VERSION 5.8 ;
BUSBITCHARS "[]" ;
DIVIDERCHAR "/" ;
UNITS
    DATABASE MICRONS 1000 ;
END UNITS

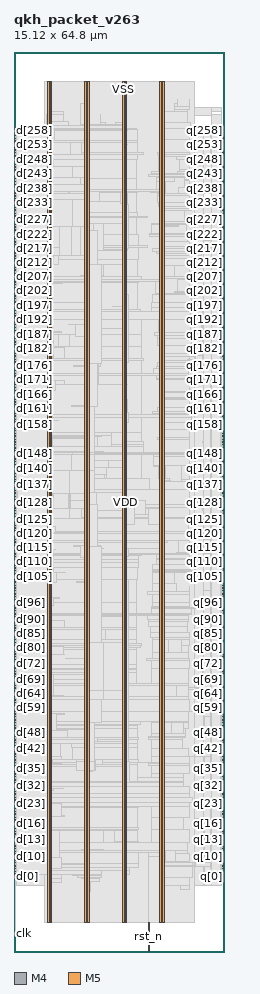
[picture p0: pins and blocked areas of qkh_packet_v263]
MACRO qkh_packet_v263
  FOREIGN qkh_packet_v263 0 0 ;
  CLASS BLOCK ;
  SIZE 15.12 BY 64.8 ;
  PIN clk
    DIRECTION INPUT ;
    USE SIGNAL ;
    PORT
      LAYER M4 ;
        RECT  0.054 1.296 0.138 1.32 ;
    END
    PORT
      LAYER M4 ;
        RECT  0.108 1.296 0.227 1.416 ;
    END
  END clk
  PIN d[0]
    DIRECTION INPUT ;
    USE SIGNAL ;
    PORT
      LAYER M4 ;
        RECT  0.054 5.424 0.138 5.448 ;
    END
  END d[0]
  PIN d[100]
    DIRECTION INPUT ;
    USE SIGNAL ;
    PORT
      LAYER M4 ;
        RECT  0.054 26.016 0.138 26.04 ;
    END
  END d[100]
  PIN d[101]
    DIRECTION INPUT ;
    USE SIGNAL ;
    PORT
      LAYER M4 ;
        RECT  0.054 26.208 0.138 26.232 ;
    END
  END d[101]
  PIN d[102]
    DIRECTION INPUT ;
    USE SIGNAL ;
    PORT
      LAYER M4 ;
        RECT  0.054 26.4 0.138 26.424 ;
    END
  END d[102]
  PIN d[103]
    DIRECTION INPUT ;
    USE SIGNAL ;
    PORT
      LAYER M4 ;
        RECT  0.054 26.64 0.138 26.664 ;
    END
  END d[103]
  PIN d[104]
    DIRECTION INPUT ;
    USE SIGNAL ;
    PORT
      LAYER M4 ;
        RECT  0.054 26.832 0.138 26.856 ;
    END
  END d[104]
  PIN d[105]
    DIRECTION INPUT ;
    USE SIGNAL ;
    PORT
      LAYER M4 ;
        RECT  0.054 27.024 0.138 27.048 ;
    END
  END d[105]
  PIN d[106]
    DIRECTION INPUT ;
    USE SIGNAL ;
    PORT
      LAYER M4 ;
        RECT  0.054 27.216 0.138 27.24 ;
    END
  END d[106]
  PIN d[107]
    DIRECTION INPUT ;
    USE SIGNAL ;
    PORT
      LAYER M4 ;
        RECT  0.054 27.456 0.138 27.48 ;
    END
  END d[107]
  PIN d[108]
    DIRECTION INPUT ;
    USE SIGNAL ;
    PORT
      LAYER M4 ;
        RECT  0.054 27.648 0.138 27.672 ;
    END
  END d[108]
  PIN d[109]
    DIRECTION INPUT ;
    USE SIGNAL ;
    PORT
      LAYER M4 ;
        RECT  0.054 27.84 0.138 27.864 ;
    END
  END d[109]
  PIN d[10]
    DIRECTION INPUT ;
    USE SIGNAL ;
    PORT
      LAYER M4 ;
        RECT  0.054 7.44 0.138 7.464 ;
    END
  END d[10]
  PIN d[110]
    DIRECTION INPUT ;
    USE SIGNAL ;
    PORT
      LAYER M4 ;
        RECT  0.054 28.08 0.138 28.104 ;
    END
  END d[110]
  PIN d[111]
    DIRECTION INPUT ;
    USE SIGNAL ;
    PORT
      LAYER M4 ;
        RECT  0.054 28.272 0.138 28.296 ;
    END
  END d[111]
  PIN d[112]
    DIRECTION INPUT ;
    USE SIGNAL ;
    PORT
      LAYER M4 ;
        RECT  0.054 28.464 0.138 28.488 ;
    END
  END d[112]
  PIN d[113]
    DIRECTION INPUT ;
    USE SIGNAL ;
    PORT
      LAYER M4 ;
        RECT  0.054 28.656 0.138 28.68 ;
    END
  END d[113]
  PIN d[114]
    DIRECTION INPUT ;
    USE SIGNAL ;
    PORT
      LAYER M4 ;
        RECT  0.054 28.896 0.138 28.92 ;
    END
  END d[114]
  PIN d[115]
    DIRECTION INPUT ;
    USE SIGNAL ;
    PORT
      LAYER M4 ;
        RECT  0.054 29.088 0.138 29.112 ;
    END
  END d[115]
  PIN d[116]
    DIRECTION INPUT ;
    USE SIGNAL ;
    PORT
      LAYER M4 ;
        RECT  0.054 29.28 0.138 29.304 ;
    END
  END d[116]
  PIN d[117]
    DIRECTION INPUT ;
    USE SIGNAL ;
    PORT
      LAYER M4 ;
        RECT  0.054 29.52 0.138 29.544 ;
    END
  END d[117]
  PIN d[118]
    DIRECTION INPUT ;
    USE SIGNAL ;
    PORT
      LAYER M4 ;
        RECT  0.054 29.712 0.138 29.736 ;
    END
  END d[118]
  PIN d[119]
    DIRECTION INPUT ;
    USE SIGNAL ;
    PORT
      LAYER M4 ;
        RECT  0.054 29.904 0.138 29.928 ;
    END
  END d[119]
  PIN d[11]
    DIRECTION INPUT ;
    USE SIGNAL ;
    PORT
      LAYER M4 ;
        RECT  0.054 7.632 0.138 7.656 ;
    END
  END d[11]
  PIN d[120]
    DIRECTION INPUT ;
    USE SIGNAL ;
    PORT
      LAYER M4 ;
        RECT  0.054 30.144 0.138 30.168 ;
    END
  END d[120]
  PIN d[121]
    DIRECTION INPUT ;
    USE SIGNAL ;
    PORT
      LAYER M4 ;
        RECT  0.054 30.336 0.138 30.36 ;
    END
  END d[121]
  PIN d[122]
    DIRECTION INPUT ;
    USE SIGNAL ;
    PORT
      LAYER M4 ;
        RECT  0.054 30.528 0.138 30.552 ;
    END
  END d[122]
  PIN d[123]
    DIRECTION INPUT ;
    USE SIGNAL ;
    PORT
      LAYER M4 ;
        RECT  0.054 30.72 0.138 30.744 ;
    END
  END d[123]
  PIN d[124]
    DIRECTION INPUT ;
    USE SIGNAL ;
    PORT
      LAYER M4 ;
        RECT  0.054 30.96 0.138 30.984 ;
    END
  END d[124]
  PIN d[125]
    DIRECTION INPUT ;
    USE SIGNAL ;
    PORT
      LAYER M4 ;
        RECT  0.054 31.152 0.138 31.176 ;
    END
  END d[125]
  PIN d[126]
    DIRECTION INPUT ;
    USE SIGNAL ;
    PORT
      LAYER M4 ;
        RECT  0.054 31.344 0.138 31.368 ;
    END
  END d[126]
  PIN d[127]
    DIRECTION INPUT ;
    USE SIGNAL ;
    PORT
      LAYER M4 ;
        RECT  0.054 31.584 0.138 31.608 ;
    END
  END d[127]
  PIN d[128]
    DIRECTION INPUT ;
    USE SIGNAL ;
    PORT
      LAYER M4 ;
        RECT  0.054 31.776 0.138 31.8 ;
    END
  END d[128]
  PIN d[129]
    DIRECTION INPUT ;
    USE SIGNAL ;
    PORT
      LAYER M4 ;
        RECT  0.054 31.968 0.138 31.992 ;
    END
  END d[129]
  PIN d[12]
    DIRECTION INPUT ;
    USE SIGNAL ;
    PORT
      LAYER M4 ;
        RECT  0.054 7.872 0.138 7.896 ;
    END
  END d[12]
  PIN d[130]
    DIRECTION INPUT ;
    USE SIGNAL ;
    PORT
      LAYER M4 ;
        RECT  0.054 32.16 0.138 32.184 ;
    END
  END d[130]
  PIN d[131]
    DIRECTION INPUT ;
    USE SIGNAL ;
    PORT
      LAYER M4 ;
        RECT  0.054 32.4 0.138 32.424 ;
    END
  END d[131]
  PIN d[132]
    DIRECTION INPUT ;
    USE SIGNAL ;
    PORT
      LAYER M4 ;
        RECT  0.054 32.592 0.138 32.616 ;
    END
  END d[132]
  PIN d[133]
    DIRECTION INPUT ;
    USE SIGNAL ;
    PORT
      LAYER M4 ;
        RECT  0.054 32.784 0.138 32.808 ;
    END
  END d[133]
  PIN d[134]
    DIRECTION INPUT ;
    USE SIGNAL ;
    PORT
      LAYER M4 ;
        RECT  0.054 33.024 0.138 33.048 ;
    END
  END d[134]
  PIN d[135]
    DIRECTION INPUT ;
    USE SIGNAL ;
    PORT
      LAYER M4 ;
        RECT  0.054 33.216 0.138 33.24 ;
    END
  END d[135]
  PIN d[136]
    DIRECTION INPUT ;
    USE SIGNAL ;
    PORT
      LAYER M4 ;
        RECT  0.054 33.408 0.138 33.432 ;
    END
  END d[136]
  PIN d[137]
    DIRECTION INPUT ;
    USE SIGNAL ;
    PORT
      LAYER M4 ;
        RECT  0.054 33.648 0.138 33.672 ;
    END
  END d[137]
  PIN d[138]
    DIRECTION INPUT ;
    USE SIGNAL ;
    PORT
      LAYER M4 ;
        RECT  0.054 33.84 0.138 33.864 ;
    END
  END d[138]
  PIN d[139]
    DIRECTION INPUT ;
    USE SIGNAL ;
    PORT
      LAYER M4 ;
        RECT  0.054 34.032 0.138 34.056 ;
    END
  END d[139]
  PIN d[13]
    DIRECTION INPUT ;
    USE SIGNAL ;
    PORT
      LAYER M4 ;
        RECT  0.054 8.064 0.138 8.088 ;
    END
  END d[13]
  PIN d[140]
    DIRECTION INPUT ;
    USE SIGNAL ;
    PORT
      LAYER M4 ;
        RECT  0.054 34.224 0.138 34.248 ;
    END
  END d[140]
  PIN d[141]
    DIRECTION INPUT ;
    USE SIGNAL ;
    PORT
      LAYER M4 ;
        RECT  0.054 34.464 0.138 34.488 ;
    END
  END d[141]
  PIN d[142]
    DIRECTION INPUT ;
    USE SIGNAL ;
    PORT
      LAYER M4 ;
        RECT  0.054 34.656 0.138 34.68 ;
    END
  END d[142]
  PIN d[143]
    DIRECTION INPUT ;
    USE SIGNAL ;
    PORT
      LAYER M4 ;
        RECT  0.054 34.848 0.138 34.872 ;
    END
  END d[143]
  PIN d[144]
    DIRECTION INPUT ;
    USE SIGNAL ;
    PORT
      LAYER M4 ;
        RECT  0.054 35.088 0.138 35.112 ;
    END
  END d[144]
  PIN d[145]
    DIRECTION INPUT ;
    USE SIGNAL ;
    PORT
      LAYER M4 ;
        RECT  0.054 35.28 0.138 35.304 ;
    END
  END d[145]
  PIN d[146]
    DIRECTION INPUT ;
    USE SIGNAL ;
    PORT
      LAYER M4 ;
        RECT  0.054 35.472 0.138 35.496 ;
    END
  END d[146]
  PIN d[147]
    DIRECTION INPUT ;
    USE SIGNAL ;
    PORT
      LAYER M4 ;
        RECT  0.054 35.664 0.138 35.688 ;
    END
  END d[147]
  PIN d[148]
    DIRECTION INPUT ;
    USE SIGNAL ;
    PORT
      LAYER M4 ;
        RECT  0.054 35.904 0.138 35.928 ;
    END
  END d[148]
  PIN d[149]
    DIRECTION INPUT ;
    USE SIGNAL ;
    PORT
      LAYER M4 ;
        RECT  0.054 36.096 0.138 36.12 ;
    END
  END d[149]
  PIN d[14]
    DIRECTION INPUT ;
    USE SIGNAL ;
    PORT
      LAYER M4 ;
        RECT  0.054 8.256 0.138 8.28 ;
    END
  END d[14]
  PIN d[150]
    DIRECTION INPUT ;
    USE SIGNAL ;
    PORT
      LAYER M4 ;
        RECT  0.054 36.288 0.138 36.312 ;
    END
  END d[150]
  PIN d[151]
    DIRECTION INPUT ;
    USE SIGNAL ;
    PORT
      LAYER M4 ;
        RECT  0.054 36.528 0.138 36.552 ;
    END
  END d[151]
  PIN d[152]
    DIRECTION INPUT ;
    USE SIGNAL ;
    PORT
      LAYER M4 ;
        RECT  0.054 36.72 0.138 36.744 ;
    END
  END d[152]
  PIN d[153]
    DIRECTION INPUT ;
    USE SIGNAL ;
    PORT
      LAYER M4 ;
        RECT  0.054 36.912 0.138 36.936 ;
    END
  END d[153]
  PIN d[154]
    DIRECTION INPUT ;
    USE SIGNAL ;
    PORT
      LAYER M4 ;
        RECT  0.054 37.152 0.138 37.176 ;
    END
  END d[154]
  PIN d[155]
    DIRECTION INPUT ;
    USE SIGNAL ;
    PORT
      LAYER M4 ;
        RECT  0.054 37.344 0.138 37.368 ;
    END
  END d[155]
  PIN d[156]
    DIRECTION INPUT ;
    USE SIGNAL ;
    PORT
      LAYER M4 ;
        RECT  0.054 37.536 0.138 37.56 ;
    END
  END d[156]
  PIN d[157]
    DIRECTION INPUT ;
    USE SIGNAL ;
    PORT
      LAYER M4 ;
        RECT  0.054 37.728 0.138 37.752 ;
    END
  END d[157]
  PIN d[158]
    DIRECTION INPUT ;
    USE SIGNAL ;
    PORT
      LAYER M4 ;
        RECT  0.054 37.968 0.138 37.992 ;
    END
  END d[158]
  PIN d[159]
    DIRECTION INPUT ;
    USE SIGNAL ;
    PORT
      LAYER M4 ;
        RECT  0.054 38.16 0.138 38.184 ;
    END
  END d[159]
  PIN d[15]
    DIRECTION INPUT ;
    USE SIGNAL ;
    PORT
      LAYER M4 ;
        RECT  0.054 8.496 0.138 8.52 ;
    END
  END d[15]
  PIN d[160]
    DIRECTION INPUT ;
    USE SIGNAL ;
    PORT
      LAYER M4 ;
        RECT  0.054 38.352 0.138 38.376 ;
    END
  END d[160]
  PIN d[161]
    DIRECTION INPUT ;
    USE SIGNAL ;
    PORT
      LAYER M4 ;
        RECT  0.054 38.592 0.138 38.616 ;
    END
  END d[161]
  PIN d[162]
    DIRECTION INPUT ;
    USE SIGNAL ;
    PORT
      LAYER M4 ;
        RECT  0.054 38.784 0.138 38.808 ;
    END
  END d[162]
  PIN d[163]
    DIRECTION INPUT ;
    USE SIGNAL ;
    PORT
      LAYER M4 ;
        RECT  0.054 38.976 0.138 39 ;
    END
  END d[163]
  PIN d[164]
    DIRECTION INPUT ;
    USE SIGNAL ;
    PORT
      LAYER M4 ;
        RECT  0.054 39.168 0.138 39.192 ;
    END
  END d[164]
  PIN d[165]
    DIRECTION INPUT ;
    USE SIGNAL ;
    PORT
      LAYER M4 ;
        RECT  0.054 39.408 0.138 39.432 ;
    END
  END d[165]
  PIN d[166]
    DIRECTION INPUT ;
    USE SIGNAL ;
    PORT
      LAYER M4 ;
        RECT  0.054 39.6 0.138 39.624 ;
    END
  END d[166]
  PIN d[167]
    DIRECTION INPUT ;
    USE SIGNAL ;
    PORT
      LAYER M4 ;
        RECT  0.054 39.792 0.138 39.816 ;
    END
  END d[167]
  PIN d[168]
    DIRECTION INPUT ;
    USE SIGNAL ;
    PORT
      LAYER M4 ;
        RECT  0.054 40.032 0.138 40.056 ;
    END
  END d[168]
  PIN d[169]
    DIRECTION INPUT ;
    USE SIGNAL ;
    PORT
      LAYER M4 ;
        RECT  0.054 40.224 0.138 40.248 ;
    END
  END d[169]
  PIN d[16]
    DIRECTION INPUT ;
    USE SIGNAL ;
    PORT
      LAYER M4 ;
        RECT  0.054 8.688 0.138 8.712 ;
    END
  END d[16]
  PIN d[170]
    DIRECTION INPUT ;
    USE SIGNAL ;
    PORT
      LAYER M4 ;
        RECT  0.054 40.416 0.138 40.44 ;
    END
  END d[170]
  PIN d[171]
    DIRECTION INPUT ;
    USE SIGNAL ;
    PORT
      LAYER M4 ;
        RECT  0.054 40.656 0.138 40.68 ;
    END
  END d[171]
  PIN d[172]
    DIRECTION INPUT ;
    USE SIGNAL ;
    PORT
      LAYER M4 ;
        RECT  0.054 40.848 0.138 40.872 ;
    END
  END d[172]
  PIN d[173]
    DIRECTION INPUT ;
    USE SIGNAL ;
    PORT
      LAYER M4 ;
        RECT  0.054 41.04 0.138 41.064 ;
    END
  END d[173]
  PIN d[174]
    DIRECTION INPUT ;
    USE SIGNAL ;
    PORT
      LAYER M4 ;
        RECT  0.054 41.232 0.138 41.256 ;
    END
  END d[174]
  PIN d[175]
    DIRECTION INPUT ;
    USE SIGNAL ;
    PORT
      LAYER M4 ;
        RECT  0.054 41.472 0.138 41.496 ;
    END
  END d[175]
  PIN d[176]
    DIRECTION INPUT ;
    USE SIGNAL ;
    PORT
      LAYER M4 ;
        RECT  0.054 41.664 0.138 41.688 ;
    END
  END d[176]
  PIN d[177]
    DIRECTION INPUT ;
    USE SIGNAL ;
    PORT
      LAYER M4 ;
        RECT  0.054 41.856 0.138 41.88 ;
    END
  END d[177]
  PIN d[178]
    DIRECTION INPUT ;
    USE SIGNAL ;
    PORT
      LAYER M4 ;
        RECT  0.054 42.096 0.138 42.12 ;
    END
  END d[178]
  PIN d[179]
    DIRECTION INPUT ;
    USE SIGNAL ;
    PORT
      LAYER M4 ;
        RECT  0.054 42.288 0.138 42.312 ;
    END
  END d[179]
  PIN d[17]
    DIRECTION INPUT ;
    USE SIGNAL ;
    PORT
      LAYER M4 ;
        RECT  0.054 8.88 0.138 8.904 ;
    END
  END d[17]
  PIN d[180]
    DIRECTION INPUT ;
    USE SIGNAL ;
    PORT
      LAYER M4 ;
        RECT  0.054 42.48 0.138 42.504 ;
    END
  END d[180]
  PIN d[181]
    DIRECTION INPUT ;
    USE SIGNAL ;
    PORT
      LAYER M4 ;
        RECT  0.054 42.672 0.138 42.696 ;
    END
  END d[181]
  PIN d[182]
    DIRECTION INPUT ;
    USE SIGNAL ;
    PORT
      LAYER M4 ;
        RECT  0.054 42.912 0.138 42.936 ;
    END
  END d[182]
  PIN d[183]
    DIRECTION INPUT ;
    USE SIGNAL ;
    PORT
      LAYER M4 ;
        RECT  0.054 43.104 0.138 43.128 ;
    END
  END d[183]
  PIN d[184]
    DIRECTION INPUT ;
    USE SIGNAL ;
    PORT
      LAYER M4 ;
        RECT  0.054 43.296 0.138 43.32 ;
    END
  END d[184]
  PIN d[185]
    DIRECTION INPUT ;
    USE SIGNAL ;
    PORT
      LAYER M4 ;
        RECT  0.054 43.536 0.138 43.56 ;
    END
  END d[185]
  PIN d[186]
    DIRECTION INPUT ;
    USE SIGNAL ;
    PORT
      LAYER M4 ;
        RECT  0.054 43.728 0.138 43.752 ;
    END
  END d[186]
  PIN d[187]
    DIRECTION INPUT ;
    USE SIGNAL ;
    PORT
      LAYER M4 ;
        RECT  0.054 43.92 0.138 43.944 ;
    END
  END d[187]
  PIN d[188]
    DIRECTION INPUT ;
    USE SIGNAL ;
    PORT
      LAYER M4 ;
        RECT  0.054 44.16 0.138 44.184 ;
    END
  END d[188]
  PIN d[189]
    DIRECTION INPUT ;
    USE SIGNAL ;
    PORT
      LAYER M4 ;
        RECT  0.054 44.352 0.138 44.376 ;
    END
  END d[189]
  PIN d[18]
    DIRECTION INPUT ;
    USE SIGNAL ;
    PORT
      LAYER M4 ;
        RECT  0.054 9.12 0.138 9.144 ;
    END
  END d[18]
  PIN d[190]
    DIRECTION INPUT ;
    USE SIGNAL ;
    PORT
      LAYER M4 ;
        RECT  0.054 44.544 0.138 44.568 ;
    END
  END d[190]
  PIN d[191]
    DIRECTION INPUT ;
    USE SIGNAL ;
    PORT
      LAYER M4 ;
        RECT  0.054 44.736 0.138 44.76 ;
    END
  END d[191]
  PIN d[192]
    DIRECTION INPUT ;
    USE SIGNAL ;
    PORT
      LAYER M4 ;
        RECT  0.054 44.976 0.138 45 ;
    END
  END d[192]
  PIN d[193]
    DIRECTION INPUT ;
    USE SIGNAL ;
    PORT
      LAYER M4 ;
        RECT  0.054 45.168 0.138 45.192 ;
    END
  END d[193]
  PIN d[194]
    DIRECTION INPUT ;
    USE SIGNAL ;
    PORT
      LAYER M4 ;
        RECT  0.054 45.36 0.138 45.384 ;
    END
  END d[194]
  PIN d[195]
    DIRECTION INPUT ;
    USE SIGNAL ;
    PORT
      LAYER M4 ;
        RECT  0.054 45.6 0.138 45.624 ;
    END
  END d[195]
  PIN d[196]
    DIRECTION INPUT ;
    USE SIGNAL ;
    PORT
      LAYER M4 ;
        RECT  0.054 45.792 0.138 45.816 ;
    END
  END d[196]
  PIN d[197]
    DIRECTION INPUT ;
    USE SIGNAL ;
    PORT
      LAYER M4 ;
        RECT  0.054 45.984 0.138 46.008 ;
    END
  END d[197]
  PIN d[198]
    DIRECTION INPUT ;
    USE SIGNAL ;
    PORT
      LAYER M4 ;
        RECT  0.054 46.176 0.138 46.2 ;
    END
  END d[198]
  PIN d[199]
    DIRECTION INPUT ;
    USE SIGNAL ;
    PORT
      LAYER M4 ;
        RECT  0.054 46.416 0.138 46.44 ;
    END
  END d[199]
  PIN d[19]
    DIRECTION INPUT ;
    USE SIGNAL ;
    PORT
      LAYER M4 ;
        RECT  0.054 9.312 0.138 9.336 ;
    END
  END d[19]
  PIN d[1]
    DIRECTION INPUT ;
    USE SIGNAL ;
    PORT
      LAYER M4 ;
        RECT  0.054 5.616 0.138 5.64 ;
    END
  END d[1]
  PIN d[200]
    DIRECTION INPUT ;
    USE SIGNAL ;
    PORT
      LAYER M4 ;
        RECT  0.054 46.608 0.138 46.632 ;
    END
  END d[200]
  PIN d[201]
    DIRECTION INPUT ;
    USE SIGNAL ;
    PORT
      LAYER M4 ;
        RECT  0.054 46.8 0.138 46.824 ;
    END
  END d[201]
  PIN d[202]
    DIRECTION INPUT ;
    USE SIGNAL ;
    PORT
      LAYER M4 ;
        RECT  0.054 47.04 0.138 47.064 ;
    END
  END d[202]
  PIN d[203]
    DIRECTION INPUT ;
    USE SIGNAL ;
    PORT
      LAYER M4 ;
        RECT  0.054 47.232 0.138 47.256 ;
    END
  END d[203]
  PIN d[204]
    DIRECTION INPUT ;
    USE SIGNAL ;
    PORT
      LAYER M4 ;
        RECT  0.054 47.424 0.138 47.448 ;
    END
  END d[204]
  PIN d[205]
    DIRECTION INPUT ;
    USE SIGNAL ;
    PORT
      LAYER M4 ;
        RECT  0.054 47.616 0.138 47.64 ;
    END
  END d[205]
  PIN d[206]
    DIRECTION INPUT ;
    USE SIGNAL ;
    PORT
      LAYER M4 ;
        RECT  0.054 47.856 0.138 47.88 ;
    END
  END d[206]
  PIN d[207]
    DIRECTION INPUT ;
    USE SIGNAL ;
    PORT
      LAYER M4 ;
        RECT  0.054 48.048 0.138 48.072 ;
    END
  END d[207]
  PIN d[208]
    DIRECTION INPUT ;
    USE SIGNAL ;
    PORT
      LAYER M4 ;
        RECT  0.054 48.24 0.138 48.264 ;
    END
  END d[208]
  PIN d[209]
    DIRECTION INPUT ;
    USE SIGNAL ;
    PORT
      LAYER M4 ;
        RECT  0.054 48.48 0.138 48.504 ;
    END
  END d[209]
  PIN d[20]
    DIRECTION INPUT ;
    USE SIGNAL ;
    PORT
      LAYER M4 ;
        RECT  0.054 9.504 0.138 9.528 ;
    END
  END d[20]
  PIN d[210]
    DIRECTION INPUT ;
    USE SIGNAL ;
    PORT
      LAYER M4 ;
        RECT  0.054 48.672 0.138 48.696 ;
    END
  END d[210]
  PIN d[211]
    DIRECTION INPUT ;
    USE SIGNAL ;
    PORT
      LAYER M4 ;
        RECT  0.054 48.864 0.138 48.888 ;
    END
  END d[211]
  PIN d[212]
    DIRECTION INPUT ;
    USE SIGNAL ;
    PORT
      LAYER M4 ;
        RECT  0.054 49.104 0.138 49.128 ;
    END
  END d[212]
  PIN d[213]
    DIRECTION INPUT ;
    USE SIGNAL ;
    PORT
      LAYER M4 ;
        RECT  0.054 49.296 0.138 49.32 ;
    END
  END d[213]
  PIN d[214]
    DIRECTION INPUT ;
    USE SIGNAL ;
    PORT
      LAYER M4 ;
        RECT  0.054 49.488 0.138 49.512 ;
    END
  END d[214]
  PIN d[215]
    DIRECTION INPUT ;
    USE SIGNAL ;
    PORT
      LAYER M4 ;
        RECT  0.054 49.68 0.138 49.704 ;
    END
  END d[215]
  PIN d[216]
    DIRECTION INPUT ;
    USE SIGNAL ;
    PORT
      LAYER M4 ;
        RECT  0.054 49.92 0.138 49.944 ;
    END
  END d[216]
  PIN d[217]
    DIRECTION INPUT ;
    USE SIGNAL ;
    PORT
      LAYER M4 ;
        RECT  0.054 50.112 0.138 50.136 ;
    END
  END d[217]
  PIN d[218]
    DIRECTION INPUT ;
    USE SIGNAL ;
    PORT
      LAYER M4 ;
        RECT  0.054 50.304 0.138 50.328 ;
    END
  END d[218]
  PIN d[219]
    DIRECTION INPUT ;
    USE SIGNAL ;
    PORT
      LAYER M4 ;
        RECT  0.054 50.544 0.138 50.568 ;
    END
  END d[219]
  PIN d[21]
    DIRECTION INPUT ;
    USE SIGNAL ;
    PORT
      LAYER M4 ;
        RECT  0.054 9.696 0.138 9.72 ;
    END
  END d[21]
  PIN d[220]
    DIRECTION INPUT ;
    USE SIGNAL ;
    PORT
      LAYER M4 ;
        RECT  0.054 50.736 0.138 50.76 ;
    END
  END d[220]
  PIN d[221]
    DIRECTION INPUT ;
    USE SIGNAL ;
    PORT
      LAYER M4 ;
        RECT  0.054 50.928 0.138 50.952 ;
    END
  END d[221]
  PIN d[222]
    DIRECTION INPUT ;
    USE SIGNAL ;
    PORT
      LAYER M4 ;
        RECT  0.054 51.12 0.138 51.144 ;
    END
  END d[222]
  PIN d[223]
    DIRECTION INPUT ;
    USE SIGNAL ;
    PORT
      LAYER M4 ;
        RECT  0.054 51.36 0.138 51.384 ;
    END
  END d[223]
  PIN d[224]
    DIRECTION INPUT ;
    USE SIGNAL ;
    PORT
      LAYER M4 ;
        RECT  0.054 51.552 0.138 51.576 ;
    END
  END d[224]
  PIN d[225]
    DIRECTION INPUT ;
    USE SIGNAL ;
    PORT
      LAYER M4 ;
        RECT  0.054 51.744 0.138 51.768 ;
    END
  END d[225]
  PIN d[226]
    DIRECTION INPUT ;
    USE SIGNAL ;
    PORT
      LAYER M4 ;
        RECT  0.054 51.984 0.138 52.008 ;
    END
  END d[226]
  PIN d[227]
    DIRECTION INPUT ;
    USE SIGNAL ;
    PORT
      LAYER M4 ;
        RECT  0.054 52.176 0.138 52.2 ;
    END
  END d[227]
  PIN d[228]
    DIRECTION INPUT ;
    USE SIGNAL ;
    PORT
      LAYER M4 ;
        RECT  0.054 52.368 0.138 52.392 ;
    END
  END d[228]
  PIN d[229]
    DIRECTION INPUT ;
    USE SIGNAL ;
    PORT
      LAYER M4 ;
        RECT  0.054 52.608 0.138 52.632 ;
    END
  END d[229]
  PIN d[22]
    DIRECTION INPUT ;
    USE SIGNAL ;
    PORT
      LAYER M4 ;
        RECT  0.054 9.936 0.138 9.96 ;
    END
  END d[22]
  PIN d[230]
    DIRECTION INPUT ;
    USE SIGNAL ;
    PORT
      LAYER M4 ;
        RECT  0.054 52.8 0.138 52.824 ;
    END
  END d[230]
  PIN d[231]
    DIRECTION INPUT ;
    USE SIGNAL ;
    PORT
      LAYER M4 ;
        RECT  0.054 52.992 0.138 53.016 ;
    END
  END d[231]
  PIN d[232]
    DIRECTION INPUT ;
    USE SIGNAL ;
    PORT
      LAYER M4 ;
        RECT  0.054 53.184 0.138 53.208 ;
    END
  END d[232]
  PIN d[233]
    DIRECTION INPUT ;
    USE SIGNAL ;
    PORT
      LAYER M4 ;
        RECT  0.054 53.424 0.138 53.448 ;
    END
  END d[233]
  PIN d[234]
    DIRECTION INPUT ;
    USE SIGNAL ;
    PORT
      LAYER M4 ;
        RECT  0.054 53.616 0.138 53.64 ;
    END
  END d[234]
  PIN d[235]
    DIRECTION INPUT ;
    USE SIGNAL ;
    PORT
      LAYER M4 ;
        RECT  0.054 53.808 0.138 53.832 ;
    END
  END d[235]
  PIN d[236]
    DIRECTION INPUT ;
    USE SIGNAL ;
    PORT
      LAYER M4 ;
        RECT  0.054 54.048 0.138 54.072 ;
    END
  END d[236]
  PIN d[237]
    DIRECTION INPUT ;
    USE SIGNAL ;
    PORT
      LAYER M4 ;
        RECT  0.054 54.24 0.138 54.264 ;
    END
  END d[237]
  PIN d[238]
    DIRECTION INPUT ;
    USE SIGNAL ;
    PORT
      LAYER M4 ;
        RECT  0.054 54.432 0.138 54.456 ;
    END
  END d[238]
  PIN d[239]
    DIRECTION INPUT ;
    USE SIGNAL ;
    PORT
      LAYER M4 ;
        RECT  0.054 54.624 0.138 54.648 ;
    END
  END d[239]
  PIN d[23]
    DIRECTION INPUT ;
    USE SIGNAL ;
    PORT
      LAYER M4 ;
        RECT  0.054 10.128 0.138 10.152 ;
    END
  END d[23]
  PIN d[240]
    DIRECTION INPUT ;
    USE SIGNAL ;
    PORT
      LAYER M4 ;
        RECT  0.054 54.864 0.138 54.888 ;
    END
  END d[240]
  PIN d[241]
    DIRECTION INPUT ;
    USE SIGNAL ;
    PORT
      LAYER M4 ;
        RECT  0.054 55.056 0.138 55.08 ;
    END
  END d[241]
  PIN d[242]
    DIRECTION INPUT ;
    USE SIGNAL ;
    PORT
      LAYER M4 ;
        RECT  0.054 55.248 0.138 55.272 ;
    END
  END d[242]
  PIN d[243]
    DIRECTION INPUT ;
    USE SIGNAL ;
    PORT
      LAYER M4 ;
        RECT  0.054 55.488 0.138 55.512 ;
    END
  END d[243]
  PIN d[244]
    DIRECTION INPUT ;
    USE SIGNAL ;
    PORT
      LAYER M4 ;
        RECT  0.054 55.68 0.138 55.704 ;
    END
  END d[244]
  PIN d[245]
    DIRECTION INPUT ;
    USE SIGNAL ;
    PORT
      LAYER M4 ;
        RECT  0.054 55.872 0.138 55.896 ;
    END
  END d[245]
  PIN d[246]
    DIRECTION INPUT ;
    USE SIGNAL ;
    PORT
      LAYER M4 ;
        RECT  0.054 56.112 0.138 56.136 ;
    END
  END d[246]
  PIN d[247]
    DIRECTION INPUT ;
    USE SIGNAL ;
    PORT
      LAYER M4 ;
        RECT  0.054 56.304 0.138 56.328 ;
    END
  END d[247]
  PIN d[248]
    DIRECTION INPUT ;
    USE SIGNAL ;
    PORT
      LAYER M4 ;
        RECT  0.054 56.496 0.138 56.52 ;
    END
  END d[248]
  PIN d[249]
    DIRECTION INPUT ;
    USE SIGNAL ;
    PORT
      LAYER M4 ;
        RECT  0.054 56.688 0.138 56.712 ;
    END
  END d[249]
  PIN d[24]
    DIRECTION INPUT ;
    USE SIGNAL ;
    PORT
      LAYER M4 ;
        RECT  0.054 10.32 0.138 10.344 ;
    END
  END d[24]
  PIN d[250]
    DIRECTION INPUT ;
    USE SIGNAL ;
    PORT
      LAYER M4 ;
        RECT  0.054 56.928 0.138 56.952 ;
    END
  END d[250]
  PIN d[251]
    DIRECTION INPUT ;
    USE SIGNAL ;
    PORT
      LAYER M4 ;
        RECT  0.054 57.12 0.138 57.144 ;
    END
  END d[251]
  PIN d[252]
    DIRECTION INPUT ;
    USE SIGNAL ;
    PORT
      LAYER M4 ;
        RECT  0.054 57.312 0.138 57.336 ;
    END
  END d[252]
  PIN d[253]
    DIRECTION INPUT ;
    USE SIGNAL ;
    PORT
      LAYER M4 ;
        RECT  0.054 57.552 0.138 57.576 ;
    END
  END d[253]
  PIN d[254]
    DIRECTION INPUT ;
    USE SIGNAL ;
    PORT
      LAYER M4 ;
        RECT  0.054 57.744 0.138 57.768 ;
    END
  END d[254]
  PIN d[255]
    DIRECTION INPUT ;
    USE SIGNAL ;
    PORT
      LAYER M4 ;
        RECT  0.054 57.936 0.138 57.96 ;
    END
  END d[255]
  PIN d[256]
    DIRECTION INPUT ;
    USE SIGNAL ;
    PORT
      LAYER M4 ;
        RECT  0.054 58.128 0.138 58.152 ;
    END
  END d[256]
  PIN d[257]
    DIRECTION INPUT ;
    USE SIGNAL ;
    PORT
      LAYER M4 ;
        RECT  0.054 58.368 0.138 58.392 ;
    END
  END d[257]
  PIN d[258]
    DIRECTION INPUT ;
    USE SIGNAL ;
    PORT
      LAYER M4 ;
        RECT  0.054 58.56 0.138 58.584 ;
    END
  END d[258]
  PIN d[259]
    DIRECTION INPUT ;
    USE SIGNAL ;
    PORT
      LAYER M4 ;
        RECT  0.054 58.752 0.138 58.776 ;
    END
  END d[259]
  PIN d[25]
    DIRECTION INPUT ;
    USE SIGNAL ;
    PORT
      LAYER M4 ;
        RECT  0.054 10.56 0.138 10.584 ;
    END
  END d[25]
  PIN d[260]
    DIRECTION INPUT ;
    USE SIGNAL ;
    PORT
      LAYER M4 ;
        RECT  0.054 58.992 0.138 59.016 ;
    END
  END d[260]
  PIN d[261]
    DIRECTION INPUT ;
    USE SIGNAL ;
    PORT
      LAYER M4 ;
        RECT  0.054 59.184 0.138 59.208 ;
    END
  END d[261]
  PIN d[262]
    DIRECTION INPUT ;
    USE SIGNAL ;
    PORT
      LAYER M4 ;
        RECT  0.054 59.376 0.138 59.4 ;
    END
  END d[262]
  PIN d[26]
    DIRECTION INPUT ;
    USE SIGNAL ;
    PORT
      LAYER M4 ;
        RECT  0.054 10.752 0.138 10.776 ;
    END
  END d[26]
  PIN d[27]
    DIRECTION INPUT ;
    USE SIGNAL ;
    PORT
      LAYER M4 ;
        RECT  0.054 10.944 0.138 10.968 ;
    END
  END d[27]
  PIN d[28]
    DIRECTION INPUT ;
    USE SIGNAL ;
    PORT
      LAYER M4 ;
        RECT  0.054 11.136 0.138 11.16 ;
    END
  END d[28]
  PIN d[29]
    DIRECTION INPUT ;
    USE SIGNAL ;
    PORT
      LAYER M4 ;
        RECT  0.054 11.376 0.138 11.4 ;
    END
  END d[29]
  PIN d[2]
    DIRECTION INPUT ;
    USE SIGNAL ;
    PORT
      LAYER M4 ;
        RECT  0.054 5.808 0.138 5.832 ;
    END
  END d[2]
  PIN d[30]
    DIRECTION INPUT ;
    USE SIGNAL ;
    PORT
      LAYER M4 ;
        RECT  0.054 11.568 0.138 11.592 ;
    END
  END d[30]
  PIN d[31]
    DIRECTION INPUT ;
    USE SIGNAL ;
    PORT
      LAYER M4 ;
        RECT  0.054 11.76 0.138 11.784 ;
    END
  END d[31]
  PIN d[32]
    DIRECTION INPUT ;
    USE SIGNAL ;
    PORT
      LAYER M4 ;
        RECT  0.054 12 0.138 12.024 ;
    END
  END d[32]
  PIN d[33]
    DIRECTION INPUT ;
    USE SIGNAL ;
    PORT
      LAYER M4 ;
        RECT  0.054 12.192 0.138 12.216 ;
    END
  END d[33]
  PIN d[34]
    DIRECTION INPUT ;
    USE SIGNAL ;
    PORT
      LAYER M4 ;
        RECT  0.054 12.384 0.138 12.408 ;
    END
  END d[34]
  PIN d[35]
    DIRECTION INPUT ;
    USE SIGNAL ;
    PORT
      LAYER M4 ;
        RECT  0.054 12.624 0.138 12.648 ;
    END
  END d[35]
  PIN d[36]
    DIRECTION INPUT ;
    USE SIGNAL ;
    PORT
      LAYER M4 ;
        RECT  0.054 12.816 0.138 12.84 ;
    END
  END d[36]
  PIN d[37]
    DIRECTION INPUT ;
    USE SIGNAL ;
    PORT
      LAYER M4 ;
        RECT  0.054 13.008 0.138 13.032 ;
    END
  END d[37]
  PIN d[38]
    DIRECTION INPUT ;
    USE SIGNAL ;
    PORT
      LAYER M4 ;
        RECT  0.054 13.2 0.138 13.224 ;
    END
  END d[38]
  PIN d[39]
    DIRECTION INPUT ;
    USE SIGNAL ;
    PORT
      LAYER M4 ;
        RECT  0.054 13.44 0.138 13.464 ;
    END
  END d[39]
  PIN d[3]
    DIRECTION INPUT ;
    USE SIGNAL ;
    PORT
      LAYER M4 ;
        RECT  0.054 6 0.138 6.024 ;
    END
  END d[3]
  PIN d[40]
    DIRECTION INPUT ;
    USE SIGNAL ;
    PORT
      LAYER M4 ;
        RECT  0.054 13.632 0.138 13.656 ;
    END
  END d[40]
  PIN d[41]
    DIRECTION INPUT ;
    USE SIGNAL ;
    PORT
      LAYER M4 ;
        RECT  0.054 13.824 0.138 13.848 ;
    END
  END d[41]
  PIN d[42]
    DIRECTION INPUT ;
    USE SIGNAL ;
    PORT
      LAYER M4 ;
        RECT  0.054 14.064 0.138 14.088 ;
    END
  END d[42]
  PIN d[43]
    DIRECTION INPUT ;
    USE SIGNAL ;
    PORT
      LAYER M4 ;
        RECT  0.054 14.256 0.138 14.28 ;
    END
  END d[43]
  PIN d[44]
    DIRECTION INPUT ;
    USE SIGNAL ;
    PORT
      LAYER M4 ;
        RECT  0.054 14.448 0.138 14.472 ;
    END
  END d[44]
  PIN d[45]
    DIRECTION INPUT ;
    USE SIGNAL ;
    PORT
      LAYER M4 ;
        RECT  0.054 14.64 0.138 14.664 ;
    END
  END d[45]
  PIN d[46]
    DIRECTION INPUT ;
    USE SIGNAL ;
    PORT
      LAYER M4 ;
        RECT  0.054 14.88 0.138 14.904 ;
    END
  END d[46]
  PIN d[47]
    DIRECTION INPUT ;
    USE SIGNAL ;
    PORT
      LAYER M4 ;
        RECT  0.054 15.072 0.138 15.096 ;
    END
  END d[47]
  PIN d[48]
    DIRECTION INPUT ;
    USE SIGNAL ;
    PORT
      LAYER M4 ;
        RECT  0.054 15.264 0.138 15.288 ;
    END
  END d[48]
  PIN d[49]
    DIRECTION INPUT ;
    USE SIGNAL ;
    PORT
      LAYER M4 ;
        RECT  0.054 15.504 0.138 15.528 ;
    END
  END d[49]
  PIN d[4]
    DIRECTION INPUT ;
    USE SIGNAL ;
    PORT
      LAYER M4 ;
        RECT  0.054 6.192 0.138 6.216 ;
    END
  END d[4]
  PIN d[50]
    DIRECTION INPUT ;
    USE SIGNAL ;
    PORT
      LAYER M4 ;
        RECT  0.054 15.696 0.138 15.72 ;
    END
  END d[50]
  PIN d[51]
    DIRECTION INPUT ;
    USE SIGNAL ;
    PORT
      LAYER M4 ;
        RECT  0.054 15.888 0.138 15.912 ;
    END
  END d[51]
  PIN d[52]
    DIRECTION INPUT ;
    USE SIGNAL ;
    PORT
      LAYER M4 ;
        RECT  0.054 16.128 0.138 16.152 ;
    END
  END d[52]
  PIN d[53]
    DIRECTION INPUT ;
    USE SIGNAL ;
    PORT
      LAYER M4 ;
        RECT  0.054 16.32 0.138 16.344 ;
    END
  END d[53]
  PIN d[54]
    DIRECTION INPUT ;
    USE SIGNAL ;
    PORT
      LAYER M4 ;
        RECT  0.054 16.512 0.138 16.536 ;
    END
  END d[54]
  PIN d[55]
    DIRECTION INPUT ;
    USE SIGNAL ;
    PORT
      LAYER M4 ;
        RECT  0.054 16.704 0.138 16.728 ;
    END
  END d[55]
  PIN d[56]
    DIRECTION INPUT ;
    USE SIGNAL ;
    PORT
      LAYER M4 ;
        RECT  0.054 16.944 0.138 16.968 ;
    END
  END d[56]
  PIN d[57]
    DIRECTION INPUT ;
    USE SIGNAL ;
    PORT
      LAYER M4 ;
        RECT  0.054 17.136 0.138 17.16 ;
    END
  END d[57]
  PIN d[58]
    DIRECTION INPUT ;
    USE SIGNAL ;
    PORT
      LAYER M4 ;
        RECT  0.054 17.328 0.138 17.352 ;
    END
  END d[58]
  PIN d[59]
    DIRECTION INPUT ;
    USE SIGNAL ;
    PORT
      LAYER M4 ;
        RECT  0.054 17.568 0.138 17.592 ;
    END
  END d[59]
  PIN d[5]
    DIRECTION INPUT ;
    USE SIGNAL ;
    PORT
      LAYER M4 ;
        RECT  0.054 6.432 0.138 6.456 ;
    END
  END d[5]
  PIN d[60]
    DIRECTION INPUT ;
    USE SIGNAL ;
    PORT
      LAYER M4 ;
        RECT  0.054 17.76 0.138 17.784 ;
    END
  END d[60]
  PIN d[61]
    DIRECTION INPUT ;
    USE SIGNAL ;
    PORT
      LAYER M4 ;
        RECT  0.054 17.952 0.138 17.976 ;
    END
  END d[61]
  PIN d[62]
    DIRECTION INPUT ;
    USE SIGNAL ;
    PORT
      LAYER M4 ;
        RECT  0.054 18.144 0.138 18.168 ;
    END
  END d[62]
  PIN d[63]
    DIRECTION INPUT ;
    USE SIGNAL ;
    PORT
      LAYER M4 ;
        RECT  0.054 18.384 0.138 18.408 ;
    END
  END d[63]
  PIN d[64]
    DIRECTION INPUT ;
    USE SIGNAL ;
    PORT
      LAYER M4 ;
        RECT  0.054 18.576 0.138 18.6 ;
    END
  END d[64]
  PIN d[65]
    DIRECTION INPUT ;
    USE SIGNAL ;
    PORT
      LAYER M4 ;
        RECT  0.054 18.768 0.138 18.792 ;
    END
  END d[65]
  PIN d[66]
    DIRECTION INPUT ;
    USE SIGNAL ;
    PORT
      LAYER M4 ;
        RECT  0.054 19.008 0.138 19.032 ;
    END
  END d[66]
  PIN d[67]
    DIRECTION INPUT ;
    USE SIGNAL ;
    PORT
      LAYER M4 ;
        RECT  0.054 19.2 0.138 19.224 ;
    END
  END d[67]
  PIN d[68]
    DIRECTION INPUT ;
    USE SIGNAL ;
    PORT
      LAYER M4 ;
        RECT  0.054 19.392 0.138 19.416 ;
    END
  END d[68]
  PIN d[69]
    DIRECTION INPUT ;
    USE SIGNAL ;
    PORT
      LAYER M4 ;
        RECT  0.054 19.632 0.138 19.656 ;
    END
  END d[69]
  PIN d[6]
    DIRECTION INPUT ;
    USE SIGNAL ;
    PORT
      LAYER M4 ;
        RECT  0.054 6.624 0.138 6.648 ;
    END
  END d[6]
  PIN d[70]
    DIRECTION INPUT ;
    USE SIGNAL ;
    PORT
      LAYER M4 ;
        RECT  0.054 19.824 0.138 19.848 ;
    END
  END d[70]
  PIN d[71]
    DIRECTION INPUT ;
    USE SIGNAL ;
    PORT
      LAYER M4 ;
        RECT  0.054 20.016 0.138 20.04 ;
    END
  END d[71]
  PIN d[72]
    DIRECTION INPUT ;
    USE SIGNAL ;
    PORT
      LAYER M4 ;
        RECT  0.054 20.208 0.138 20.232 ;
    END
  END d[72]
  PIN d[73]
    DIRECTION INPUT ;
    USE SIGNAL ;
    PORT
      LAYER M4 ;
        RECT  0.054 20.448 0.138 20.472 ;
    END
  END d[73]
  PIN d[74]
    DIRECTION INPUT ;
    USE SIGNAL ;
    PORT
      LAYER M4 ;
        RECT  0.054 20.64 0.138 20.664 ;
    END
  END d[74]
  PIN d[75]
    DIRECTION INPUT ;
    USE SIGNAL ;
    PORT
      LAYER M4 ;
        RECT  0.054 20.832 0.138 20.856 ;
    END
  END d[75]
  PIN d[76]
    DIRECTION INPUT ;
    USE SIGNAL ;
    PORT
      LAYER M4 ;
        RECT  0.054 21.072 0.138 21.096 ;
    END
  END d[76]
  PIN d[77]
    DIRECTION INPUT ;
    USE SIGNAL ;
    PORT
      LAYER M4 ;
        RECT  0.054 21.264 0.138 21.288 ;
    END
  END d[77]
  PIN d[78]
    DIRECTION INPUT ;
    USE SIGNAL ;
    PORT
      LAYER M4 ;
        RECT  0.054 21.456 0.138 21.48 ;
    END
  END d[78]
  PIN d[79]
    DIRECTION INPUT ;
    USE SIGNAL ;
    PORT
      LAYER M4 ;
        RECT  0.054 21.648 0.138 21.672 ;
    END
  END d[79]
  PIN d[7]
    DIRECTION INPUT ;
    USE SIGNAL ;
    PORT
      LAYER M4 ;
        RECT  0.054 6.816 0.138 6.84 ;
    END
  END d[7]
  PIN d[80]
    DIRECTION INPUT ;
    USE SIGNAL ;
    PORT
      LAYER M4 ;
        RECT  0.054 21.888 0.138 21.912 ;
    END
  END d[80]
  PIN d[81]
    DIRECTION INPUT ;
    USE SIGNAL ;
    PORT
      LAYER M4 ;
        RECT  0.054 22.08 0.138 22.104 ;
    END
  END d[81]
  PIN d[82]
    DIRECTION INPUT ;
    USE SIGNAL ;
    PORT
      LAYER M4 ;
        RECT  0.054 22.272 0.138 22.296 ;
    END
  END d[82]
  PIN d[83]
    DIRECTION INPUT ;
    USE SIGNAL ;
    PORT
      LAYER M4 ;
        RECT  0.054 22.512 0.138 22.536 ;
    END
  END d[83]
  PIN d[84]
    DIRECTION INPUT ;
    USE SIGNAL ;
    PORT
      LAYER M4 ;
        RECT  0.054 22.704 0.138 22.728 ;
    END
  END d[84]
  PIN d[85]
    DIRECTION INPUT ;
    USE SIGNAL ;
    PORT
      LAYER M4 ;
        RECT  0.054 22.896 0.138 22.92 ;
    END
  END d[85]
  PIN d[86]
    DIRECTION INPUT ;
    USE SIGNAL ;
    PORT
      LAYER M4 ;
        RECT  0.054 23.136 0.138 23.16 ;
    END
  END d[86]
  PIN d[87]
    DIRECTION INPUT ;
    USE SIGNAL ;
    PORT
      LAYER M4 ;
        RECT  0.054 23.328 0.138 23.352 ;
    END
  END d[87]
  PIN d[88]
    DIRECTION INPUT ;
    USE SIGNAL ;
    PORT
      LAYER M4 ;
        RECT  0.054 23.52 0.138 23.544 ;
    END
  END d[88]
  PIN d[89]
    DIRECTION INPUT ;
    USE SIGNAL ;
    PORT
      LAYER M4 ;
        RECT  0.054 23.712 0.138 23.736 ;
    END
  END d[89]
  PIN d[8]
    DIRECTION INPUT ;
    USE SIGNAL ;
    PORT
      LAYER M4 ;
        RECT  0.054 7.056 0.138 7.08 ;
    END
  END d[8]
  PIN d[90]
    DIRECTION INPUT ;
    USE SIGNAL ;
    PORT
      LAYER M4 ;
        RECT  0.054 23.952 0.138 23.976 ;
    END
  END d[90]
  PIN d[91]
    DIRECTION INPUT ;
    USE SIGNAL ;
    PORT
      LAYER M4 ;
        RECT  0.054 24.144 0.138 24.168 ;
    END
  END d[91]
  PIN d[92]
    DIRECTION INPUT ;
    USE SIGNAL ;
    PORT
      LAYER M4 ;
        RECT  0.054 24.336 0.138 24.36 ;
    END
  END d[92]
  PIN d[93]
    DIRECTION INPUT ;
    USE SIGNAL ;
    PORT
      LAYER M4 ;
        RECT  0.054 24.576 0.138 24.6 ;
    END
  END d[93]
  PIN d[94]
    DIRECTION INPUT ;
    USE SIGNAL ;
    PORT
      LAYER M4 ;
        RECT  0.054 24.768 0.138 24.792 ;
    END
  END d[94]
  PIN d[95]
    DIRECTION INPUT ;
    USE SIGNAL ;
    PORT
      LAYER M4 ;
        RECT  0.054 24.96 0.138 24.984 ;
    END
  END d[95]
  PIN d[96]
    DIRECTION INPUT ;
    USE SIGNAL ;
    PORT
      LAYER M4 ;
        RECT  0.054 25.152 0.138 25.176 ;
    END
  END d[96]
  PIN d[97]
    DIRECTION INPUT ;
    USE SIGNAL ;
    PORT
      LAYER M4 ;
        RECT  0.054 25.392 0.138 25.416 ;
    END
  END d[97]
  PIN d[98]
    DIRECTION INPUT ;
    USE SIGNAL ;
    PORT
      LAYER M4 ;
        RECT  0.054 25.584 0.138 25.608 ;
    END
  END d[98]
  PIN d[99]
    DIRECTION INPUT ;
    USE SIGNAL ;
    PORT
      LAYER M4 ;
        RECT  0.054 25.776 0.138 25.8 ;
    END
  END d[99]
  PIN d[9]
    DIRECTION INPUT ;
    USE SIGNAL ;
    PORT
      LAYER M4 ;
        RECT  0.054 7.248 0.138 7.272 ;
    END
  END d[9]
  PIN q[0]
    DIRECTION OUTPUT ;
    USE SIGNAL ;
    PORT
      LAYER M4 ;
        RECT  14.982 5.424 15.066 5.448 ;
    END
  END q[0]
  PIN q[100]
    DIRECTION OUTPUT ;
    USE SIGNAL ;
    PORT
      LAYER M4 ;
        RECT  14.982 26.016 15.066 26.04 ;
    END
  END q[100]
  PIN q[101]
    DIRECTION OUTPUT ;
    USE SIGNAL ;
    PORT
      LAYER M4 ;
        RECT  14.982 26.208 15.066 26.232 ;
    END
  END q[101]
  PIN q[102]
    DIRECTION OUTPUT ;
    USE SIGNAL ;
    PORT
      LAYER M4 ;
        RECT  14.982 26.4 15.066 26.424 ;
    END
  END q[102]
  PIN q[103]
    DIRECTION OUTPUT ;
    USE SIGNAL ;
    PORT
      LAYER M4 ;
        RECT  14.982 26.64 15.066 26.664 ;
    END
  END q[103]
  PIN q[104]
    DIRECTION OUTPUT ;
    USE SIGNAL ;
    PORT
      LAYER M4 ;
        RECT  14.982 26.832 15.066 26.856 ;
    END
  END q[104]
  PIN q[105]
    DIRECTION OUTPUT ;
    USE SIGNAL ;
    PORT
      LAYER M4 ;
        RECT  14.982 27.024 15.066 27.048 ;
    END
  END q[105]
  PIN q[106]
    DIRECTION OUTPUT ;
    USE SIGNAL ;
    PORT
      LAYER M4 ;
        RECT  14.982 27.216 15.066 27.24 ;
    END
  END q[106]
  PIN q[107]
    DIRECTION OUTPUT ;
    USE SIGNAL ;
    PORT
      LAYER M4 ;
        RECT  14.982 27.456 15.066 27.48 ;
    END
  END q[107]
  PIN q[108]
    DIRECTION OUTPUT ;
    USE SIGNAL ;
    PORT
      LAYER M4 ;
        RECT  14.982 27.648 15.066 27.672 ;
    END
  END q[108]
  PIN q[109]
    DIRECTION OUTPUT ;
    USE SIGNAL ;
    PORT
      LAYER M4 ;
        RECT  14.982 27.84 15.066 27.864 ;
    END
  END q[109]
  PIN q[10]
    DIRECTION OUTPUT ;
    USE SIGNAL ;
    PORT
      LAYER M4 ;
        RECT  14.982 7.44 15.066 7.464 ;
    END
  END q[10]
  PIN q[110]
    DIRECTION OUTPUT ;
    USE SIGNAL ;
    PORT
      LAYER M4 ;
        RECT  14.982 28.08 15.066 28.104 ;
    END
  END q[110]
  PIN q[111]
    DIRECTION OUTPUT ;
    USE SIGNAL ;
    PORT
      LAYER M4 ;
        RECT  14.982 28.272 15.066 28.296 ;
    END
  END q[111]
  PIN q[112]
    DIRECTION OUTPUT ;
    USE SIGNAL ;
    PORT
      LAYER M4 ;
        RECT  14.982 28.464 15.066 28.488 ;
    END
  END q[112]
  PIN q[113]
    DIRECTION OUTPUT ;
    USE SIGNAL ;
    PORT
      LAYER M4 ;
        RECT  14.982 28.656 15.066 28.68 ;
    END
  END q[113]
  PIN q[114]
    DIRECTION OUTPUT ;
    USE SIGNAL ;
    PORT
      LAYER M4 ;
        RECT  14.982 28.896 15.066 28.92 ;
    END
  END q[114]
  PIN q[115]
    DIRECTION OUTPUT ;
    USE SIGNAL ;
    PORT
      LAYER M4 ;
        RECT  14.982 29.088 15.066 29.112 ;
    END
  END q[115]
  PIN q[116]
    DIRECTION OUTPUT ;
    USE SIGNAL ;
    PORT
      LAYER M4 ;
        RECT  14.982 29.28 15.066 29.304 ;
    END
  END q[116]
  PIN q[117]
    DIRECTION OUTPUT ;
    USE SIGNAL ;
    PORT
      LAYER M4 ;
        RECT  14.982 29.52 15.066 29.544 ;
    END
  END q[117]
  PIN q[118]
    DIRECTION OUTPUT ;
    USE SIGNAL ;
    PORT
      LAYER M4 ;
        RECT  14.982 29.712 15.066 29.736 ;
    END
  END q[118]
  PIN q[119]
    DIRECTION OUTPUT ;
    USE SIGNAL ;
    PORT
      LAYER M4 ;
        RECT  14.982 29.904 15.066 29.928 ;
    END
  END q[119]
  PIN q[11]
    DIRECTION OUTPUT ;
    USE SIGNAL ;
    PORT
      LAYER M4 ;
        RECT  14.982 7.632 15.066 7.656 ;
    END
  END q[11]
  PIN q[120]
    DIRECTION OUTPUT ;
    USE SIGNAL ;
    PORT
      LAYER M4 ;
        RECT  14.982 30.144 15.066 30.168 ;
    END
  END q[120]
  PIN q[121]
    DIRECTION OUTPUT ;
    USE SIGNAL ;
    PORT
      LAYER M4 ;
        RECT  14.982 30.336 15.066 30.36 ;
    END
  END q[121]
  PIN q[122]
    DIRECTION OUTPUT ;
    USE SIGNAL ;
    PORT
      LAYER M4 ;
        RECT  14.982 30.528 15.066 30.552 ;
    END
  END q[122]
  PIN q[123]
    DIRECTION OUTPUT ;
    USE SIGNAL ;
    PORT
      LAYER M4 ;
        RECT  14.982 30.72 15.066 30.744 ;
    END
  END q[123]
  PIN q[124]
    DIRECTION OUTPUT ;
    USE SIGNAL ;
    PORT
      LAYER M4 ;
        RECT  14.982 30.96 15.066 30.984 ;
    END
  END q[124]
  PIN q[125]
    DIRECTION OUTPUT ;
    USE SIGNAL ;
    PORT
      LAYER M4 ;
        RECT  14.982 31.152 15.066 31.176 ;
    END
  END q[125]
  PIN q[126]
    DIRECTION OUTPUT ;
    USE SIGNAL ;
    PORT
      LAYER M4 ;
        RECT  14.982 31.344 15.066 31.368 ;
    END
  END q[126]
  PIN q[127]
    DIRECTION OUTPUT ;
    USE SIGNAL ;
    PORT
      LAYER M4 ;
        RECT  14.982 31.584 15.066 31.608 ;
    END
  END q[127]
  PIN q[128]
    DIRECTION OUTPUT ;
    USE SIGNAL ;
    PORT
      LAYER M4 ;
        RECT  14.982 31.776 15.066 31.8 ;
    END
  END q[128]
  PIN q[129]
    DIRECTION OUTPUT ;
    USE SIGNAL ;
    PORT
      LAYER M4 ;
        RECT  14.982 31.968 15.066 31.992 ;
    END
  END q[129]
  PIN q[12]
    DIRECTION OUTPUT ;
    USE SIGNAL ;
    PORT
      LAYER M4 ;
        RECT  14.982 7.872 15.066 7.896 ;
    END
  END q[12]
  PIN q[130]
    DIRECTION OUTPUT ;
    USE SIGNAL ;
    PORT
      LAYER M4 ;
        RECT  14.982 32.16 15.066 32.184 ;
    END
  END q[130]
  PIN q[131]
    DIRECTION OUTPUT ;
    USE SIGNAL ;
    PORT
      LAYER M4 ;
        RECT  14.982 32.4 15.066 32.424 ;
    END
  END q[131]
  PIN q[132]
    DIRECTION OUTPUT ;
    USE SIGNAL ;
    PORT
      LAYER M4 ;
        RECT  14.982 32.592 15.066 32.616 ;
    END
  END q[132]
  PIN q[133]
    DIRECTION OUTPUT ;
    USE SIGNAL ;
    PORT
      LAYER M4 ;
        RECT  14.982 32.784 15.066 32.808 ;
    END
  END q[133]
  PIN q[134]
    DIRECTION OUTPUT ;
    USE SIGNAL ;
    PORT
      LAYER M4 ;
        RECT  14.982 33.024 15.066 33.048 ;
    END
  END q[134]
  PIN q[135]
    DIRECTION OUTPUT ;
    USE SIGNAL ;
    PORT
      LAYER M4 ;
        RECT  14.982 33.216 15.066 33.24 ;
    END
  END q[135]
  PIN q[136]
    DIRECTION OUTPUT ;
    USE SIGNAL ;
    PORT
      LAYER M4 ;
        RECT  14.982 33.408 15.066 33.432 ;
    END
  END q[136]
  PIN q[137]
    DIRECTION OUTPUT ;
    USE SIGNAL ;
    PORT
      LAYER M4 ;
        RECT  14.982 33.648 15.066 33.672 ;
    END
  END q[137]
  PIN q[138]
    DIRECTION OUTPUT ;
    USE SIGNAL ;
    PORT
      LAYER M4 ;
        RECT  14.982 33.84 15.066 33.864 ;
    END
  END q[138]
  PIN q[139]
    DIRECTION OUTPUT ;
    USE SIGNAL ;
    PORT
      LAYER M4 ;
        RECT  14.982 34.032 15.066 34.056 ;
    END
  END q[139]
  PIN q[13]
    DIRECTION OUTPUT ;
    USE SIGNAL ;
    PORT
      LAYER M4 ;
        RECT  14.982 8.064 15.066 8.088 ;
    END
  END q[13]
  PIN q[140]
    DIRECTION OUTPUT ;
    USE SIGNAL ;
    PORT
      LAYER M4 ;
        RECT  14.982 34.224 15.066 34.248 ;
    END
  END q[140]
  PIN q[141]
    DIRECTION OUTPUT ;
    USE SIGNAL ;
    PORT
      LAYER M4 ;
        RECT  14.982 34.464 15.066 34.488 ;
    END
  END q[141]
  PIN q[142]
    DIRECTION OUTPUT ;
    USE SIGNAL ;
    PORT
      LAYER M4 ;
        RECT  14.982 34.656 15.066 34.68 ;
    END
  END q[142]
  PIN q[143]
    DIRECTION OUTPUT ;
    USE SIGNAL ;
    PORT
      LAYER M4 ;
        RECT  14.982 34.848 15.066 34.872 ;
    END
  END q[143]
  PIN q[144]
    DIRECTION OUTPUT ;
    USE SIGNAL ;
    PORT
      LAYER M4 ;
        RECT  14.982 35.088 15.066 35.112 ;
    END
  END q[144]
  PIN q[145]
    DIRECTION OUTPUT ;
    USE SIGNAL ;
    PORT
      LAYER M4 ;
        RECT  14.982 35.28 15.066 35.304 ;
    END
  END q[145]
  PIN q[146]
    DIRECTION OUTPUT ;
    USE SIGNAL ;
    PORT
      LAYER M4 ;
        RECT  14.982 35.472 15.066 35.496 ;
    END
  END q[146]
  PIN q[147]
    DIRECTION OUTPUT ;
    USE SIGNAL ;
    PORT
      LAYER M4 ;
        RECT  14.982 35.664 15.066 35.688 ;
    END
  END q[147]
  PIN q[148]
    DIRECTION OUTPUT ;
    USE SIGNAL ;
    PORT
      LAYER M4 ;
        RECT  14.982 35.904 15.066 35.928 ;
    END
  END q[148]
  PIN q[149]
    DIRECTION OUTPUT ;
    USE SIGNAL ;
    PORT
      LAYER M4 ;
        RECT  14.982 36.096 15.066 36.12 ;
    END
  END q[149]
  PIN q[14]
    DIRECTION OUTPUT ;
    USE SIGNAL ;
    PORT
      LAYER M4 ;
        RECT  14.982 8.256 15.066 8.28 ;
    END
  END q[14]
  PIN q[150]
    DIRECTION OUTPUT ;
    USE SIGNAL ;
    PORT
      LAYER M4 ;
        RECT  14.982 36.288 15.066 36.312 ;
    END
  END q[150]
  PIN q[151]
    DIRECTION OUTPUT ;
    USE SIGNAL ;
    PORT
      LAYER M4 ;
        RECT  14.982 36.528 15.066 36.552 ;
    END
  END q[151]
  PIN q[152]
    DIRECTION OUTPUT ;
    USE SIGNAL ;
    PORT
      LAYER M4 ;
        RECT  14.982 36.72 15.066 36.744 ;
    END
  END q[152]
  PIN q[153]
    DIRECTION OUTPUT ;
    USE SIGNAL ;
    PORT
      LAYER M4 ;
        RECT  14.982 36.912 15.066 36.936 ;
    END
  END q[153]
  PIN q[154]
    DIRECTION OUTPUT ;
    USE SIGNAL ;
    PORT
      LAYER M4 ;
        RECT  14.982 37.152 15.066 37.176 ;
    END
  END q[154]
  PIN q[155]
    DIRECTION OUTPUT ;
    USE SIGNAL ;
    PORT
      LAYER M4 ;
        RECT  14.982 37.344 15.066 37.368 ;
    END
  END q[155]
  PIN q[156]
    DIRECTION OUTPUT ;
    USE SIGNAL ;
    PORT
      LAYER M4 ;
        RECT  14.982 37.536 15.066 37.56 ;
    END
  END q[156]
  PIN q[157]
    DIRECTION OUTPUT ;
    USE SIGNAL ;
    PORT
      LAYER M4 ;
        RECT  14.982 37.728 15.066 37.752 ;
    END
  END q[157]
  PIN q[158]
    DIRECTION OUTPUT ;
    USE SIGNAL ;
    PORT
      LAYER M4 ;
        RECT  14.982 37.968 15.066 37.992 ;
    END
  END q[158]
  PIN q[159]
    DIRECTION OUTPUT ;
    USE SIGNAL ;
    PORT
      LAYER M4 ;
        RECT  14.982 38.16 15.066 38.184 ;
    END
  END q[159]
  PIN q[15]
    DIRECTION OUTPUT ;
    USE SIGNAL ;
    PORT
      LAYER M4 ;
        RECT  14.982 8.496 15.066 8.52 ;
    END
  END q[15]
  PIN q[160]
    DIRECTION OUTPUT ;
    USE SIGNAL ;
    PORT
      LAYER M4 ;
        RECT  14.982 38.352 15.066 38.376 ;
    END
  END q[160]
  PIN q[161]
    DIRECTION OUTPUT ;
    USE SIGNAL ;
    PORT
      LAYER M4 ;
        RECT  14.982 38.592 15.066 38.616 ;
    END
  END q[161]
  PIN q[162]
    DIRECTION OUTPUT ;
    USE SIGNAL ;
    PORT
      LAYER M4 ;
        RECT  14.982 38.784 15.066 38.808 ;
    END
  END q[162]
  PIN q[163]
    DIRECTION OUTPUT ;
    USE SIGNAL ;
    PORT
      LAYER M4 ;
        RECT  14.982 38.976 15.066 39 ;
    END
  END q[163]
  PIN q[164]
    DIRECTION OUTPUT ;
    USE SIGNAL ;
    PORT
      LAYER M4 ;
        RECT  14.982 39.168 15.066 39.192 ;
    END
  END q[164]
  PIN q[165]
    DIRECTION OUTPUT ;
    USE SIGNAL ;
    PORT
      LAYER M4 ;
        RECT  14.982 39.408 15.066 39.432 ;
    END
  END q[165]
  PIN q[166]
    DIRECTION OUTPUT ;
    USE SIGNAL ;
    PORT
      LAYER M4 ;
        RECT  14.982 39.6 15.066 39.624 ;
    END
  END q[166]
  PIN q[167]
    DIRECTION OUTPUT ;
    USE SIGNAL ;
    PORT
      LAYER M4 ;
        RECT  14.982 39.792 15.066 39.816 ;
    END
  END q[167]
  PIN q[168]
    DIRECTION OUTPUT ;
    USE SIGNAL ;
    PORT
      LAYER M4 ;
        RECT  14.982 40.032 15.066 40.056 ;
    END
  END q[168]
  PIN q[169]
    DIRECTION OUTPUT ;
    USE SIGNAL ;
    PORT
      LAYER M4 ;
        RECT  14.982 40.224 15.066 40.248 ;
    END
  END q[169]
  PIN q[16]
    DIRECTION OUTPUT ;
    USE SIGNAL ;
    PORT
      LAYER M4 ;
        RECT  14.982 8.688 15.066 8.712 ;
    END
  END q[16]
  PIN q[170]
    DIRECTION OUTPUT ;
    USE SIGNAL ;
    PORT
      LAYER M4 ;
        RECT  14.982 40.416 15.066 40.44 ;
    END
  END q[170]
  PIN q[171]
    DIRECTION OUTPUT ;
    USE SIGNAL ;
    PORT
      LAYER M4 ;
        RECT  14.982 40.656 15.066 40.68 ;
    END
  END q[171]
  PIN q[172]
    DIRECTION OUTPUT ;
    USE SIGNAL ;
    PORT
      LAYER M4 ;
        RECT  14.982 40.848 15.066 40.872 ;
    END
  END q[172]
  PIN q[173]
    DIRECTION OUTPUT ;
    USE SIGNAL ;
    PORT
      LAYER M4 ;
        RECT  14.982 41.04 15.066 41.064 ;
    END
  END q[173]
  PIN q[174]
    DIRECTION OUTPUT ;
    USE SIGNAL ;
    PORT
      LAYER M4 ;
        RECT  14.982 41.232 15.066 41.256 ;
    END
  END q[174]
  PIN q[175]
    DIRECTION OUTPUT ;
    USE SIGNAL ;
    PORT
      LAYER M4 ;
        RECT  14.982 41.472 15.066 41.496 ;
    END
  END q[175]
  PIN q[176]
    DIRECTION OUTPUT ;
    USE SIGNAL ;
    PORT
      LAYER M4 ;
        RECT  14.982 41.664 15.066 41.688 ;
    END
  END q[176]
  PIN q[177]
    DIRECTION OUTPUT ;
    USE SIGNAL ;
    PORT
      LAYER M4 ;
        RECT  14.982 41.856 15.066 41.88 ;
    END
  END q[177]
  PIN q[178]
    DIRECTION OUTPUT ;
    USE SIGNAL ;
    PORT
      LAYER M4 ;
        RECT  14.982 42.096 15.066 42.12 ;
    END
  END q[178]
  PIN q[179]
    DIRECTION OUTPUT ;
    USE SIGNAL ;
    PORT
      LAYER M4 ;
        RECT  14.982 42.288 15.066 42.312 ;
    END
  END q[179]
  PIN q[17]
    DIRECTION OUTPUT ;
    USE SIGNAL ;
    PORT
      LAYER M4 ;
        RECT  14.982 8.88 15.066 8.904 ;
    END
  END q[17]
  PIN q[180]
    DIRECTION OUTPUT ;
    USE SIGNAL ;
    PORT
      LAYER M4 ;
        RECT  14.982 42.48 15.066 42.504 ;
    END
  END q[180]
  PIN q[181]
    DIRECTION OUTPUT ;
    USE SIGNAL ;
    PORT
      LAYER M4 ;
        RECT  14.982 42.672 15.066 42.696 ;
    END
  END q[181]
  PIN q[182]
    DIRECTION OUTPUT ;
    USE SIGNAL ;
    PORT
      LAYER M4 ;
        RECT  14.982 42.912 15.066 42.936 ;
    END
  END q[182]
  PIN q[183]
    DIRECTION OUTPUT ;
    USE SIGNAL ;
    PORT
      LAYER M4 ;
        RECT  14.982 43.104 15.066 43.128 ;
    END
  END q[183]
  PIN q[184]
    DIRECTION OUTPUT ;
    USE SIGNAL ;
    PORT
      LAYER M4 ;
        RECT  14.982 43.296 15.066 43.32 ;
    END
  END q[184]
  PIN q[185]
    DIRECTION OUTPUT ;
    USE SIGNAL ;
    PORT
      LAYER M4 ;
        RECT  14.982 43.536 15.066 43.56 ;
    END
  END q[185]
  PIN q[186]
    DIRECTION OUTPUT ;
    USE SIGNAL ;
    PORT
      LAYER M4 ;
        RECT  14.982 43.728 15.066 43.752 ;
    END
  END q[186]
  PIN q[187]
    DIRECTION OUTPUT ;
    USE SIGNAL ;
    PORT
      LAYER M4 ;
        RECT  14.982 43.92 15.066 43.944 ;
    END
  END q[187]
  PIN q[188]
    DIRECTION OUTPUT ;
    USE SIGNAL ;
    PORT
      LAYER M4 ;
        RECT  14.982 44.16 15.066 44.184 ;
    END
  END q[188]
  PIN q[189]
    DIRECTION OUTPUT ;
    USE SIGNAL ;
    PORT
      LAYER M4 ;
        RECT  14.982 44.352 15.066 44.376 ;
    END
  END q[189]
  PIN q[18]
    DIRECTION OUTPUT ;
    USE SIGNAL ;
    PORT
      LAYER M4 ;
        RECT  14.982 9.12 15.066 9.144 ;
    END
  END q[18]
  PIN q[190]
    DIRECTION OUTPUT ;
    USE SIGNAL ;
    PORT
      LAYER M4 ;
        RECT  14.982 44.544 15.066 44.568 ;
    END
  END q[190]
  PIN q[191]
    DIRECTION OUTPUT ;
    USE SIGNAL ;
    PORT
      LAYER M4 ;
        RECT  14.982 44.736 15.066 44.76 ;
    END
  END q[191]
  PIN q[192]
    DIRECTION OUTPUT ;
    USE SIGNAL ;
    PORT
      LAYER M4 ;
        RECT  14.982 44.976 15.066 45 ;
    END
  END q[192]
  PIN q[193]
    DIRECTION OUTPUT ;
    USE SIGNAL ;
    PORT
      LAYER M4 ;
        RECT  14.982 45.168 15.066 45.192 ;
    END
  END q[193]
  PIN q[194]
    DIRECTION OUTPUT ;
    USE SIGNAL ;
    PORT
      LAYER M4 ;
        RECT  14.982 45.36 15.066 45.384 ;
    END
  END q[194]
  PIN q[195]
    DIRECTION OUTPUT ;
    USE SIGNAL ;
    PORT
      LAYER M4 ;
        RECT  14.982 45.6 15.066 45.624 ;
    END
  END q[195]
  PIN q[196]
    DIRECTION OUTPUT ;
    USE SIGNAL ;
    PORT
      LAYER M4 ;
        RECT  14.982 45.792 15.066 45.816 ;
    END
  END q[196]
  PIN q[197]
    DIRECTION OUTPUT ;
    USE SIGNAL ;
    PORT
      LAYER M4 ;
        RECT  14.982 45.984 15.066 46.008 ;
    END
  END q[197]
  PIN q[198]
    DIRECTION OUTPUT ;
    USE SIGNAL ;
    PORT
      LAYER M4 ;
        RECT  14.982 46.176 15.066 46.2 ;
    END
  END q[198]
  PIN q[199]
    DIRECTION OUTPUT ;
    USE SIGNAL ;
    PORT
      LAYER M4 ;
        RECT  14.982 46.416 15.066 46.44 ;
    END
  END q[199]
  PIN q[19]
    DIRECTION OUTPUT ;
    USE SIGNAL ;
    PORT
      LAYER M4 ;
        RECT  14.982 9.312 15.066 9.336 ;
    END
  END q[19]
  PIN q[1]
    DIRECTION OUTPUT ;
    USE SIGNAL ;
    PORT
      LAYER M4 ;
        RECT  14.982 5.616 15.066 5.64 ;
    END
  END q[1]
  PIN q[200]
    DIRECTION OUTPUT ;
    USE SIGNAL ;
    PORT
      LAYER M4 ;
        RECT  14.982 46.608 15.066 46.632 ;
    END
  END q[200]
  PIN q[201]
    DIRECTION OUTPUT ;
    USE SIGNAL ;
    PORT
      LAYER M4 ;
        RECT  14.982 46.8 15.066 46.824 ;
    END
  END q[201]
  PIN q[202]
    DIRECTION OUTPUT ;
    USE SIGNAL ;
    PORT
      LAYER M4 ;
        RECT  14.982 47.04 15.066 47.064 ;
    END
  END q[202]
  PIN q[203]
    DIRECTION OUTPUT ;
    USE SIGNAL ;
    PORT
      LAYER M4 ;
        RECT  14.982 47.232 15.066 47.256 ;
    END
  END q[203]
  PIN q[204]
    DIRECTION OUTPUT ;
    USE SIGNAL ;
    PORT
      LAYER M4 ;
        RECT  14.982 47.424 15.066 47.448 ;
    END
  END q[204]
  PIN q[205]
    DIRECTION OUTPUT ;
    USE SIGNAL ;
    PORT
      LAYER M4 ;
        RECT  14.982 47.616 15.066 47.64 ;
    END
  END q[205]
  PIN q[206]
    DIRECTION OUTPUT ;
    USE SIGNAL ;
    PORT
      LAYER M4 ;
        RECT  14.982 47.856 15.066 47.88 ;
    END
  END q[206]
  PIN q[207]
    DIRECTION OUTPUT ;
    USE SIGNAL ;
    PORT
      LAYER M4 ;
        RECT  14.982 48.048 15.066 48.072 ;
    END
  END q[207]
  PIN q[208]
    DIRECTION OUTPUT ;
    USE SIGNAL ;
    PORT
      LAYER M4 ;
        RECT  14.982 48.24 15.066 48.264 ;
    END
  END q[208]
  PIN q[209]
    DIRECTION OUTPUT ;
    USE SIGNAL ;
    PORT
      LAYER M4 ;
        RECT  14.982 48.48 15.066 48.504 ;
    END
  END q[209]
  PIN q[20]
    DIRECTION OUTPUT ;
    USE SIGNAL ;
    PORT
      LAYER M4 ;
        RECT  14.982 9.504 15.066 9.528 ;
    END
  END q[20]
  PIN q[210]
    DIRECTION OUTPUT ;
    USE SIGNAL ;
    PORT
      LAYER M4 ;
        RECT  14.982 48.672 15.066 48.696 ;
    END
  END q[210]
  PIN q[211]
    DIRECTION OUTPUT ;
    USE SIGNAL ;
    PORT
      LAYER M4 ;
        RECT  14.982 48.864 15.066 48.888 ;
    END
  END q[211]
  PIN q[212]
    DIRECTION OUTPUT ;
    USE SIGNAL ;
    PORT
      LAYER M4 ;
        RECT  14.982 49.104 15.066 49.128 ;
    END
  END q[212]
  PIN q[213]
    DIRECTION OUTPUT ;
    USE SIGNAL ;
    PORT
      LAYER M4 ;
        RECT  14.982 49.296 15.066 49.32 ;
    END
  END q[213]
  PIN q[214]
    DIRECTION OUTPUT ;
    USE SIGNAL ;
    PORT
      LAYER M4 ;
        RECT  14.982 49.488 15.066 49.512 ;
    END
  END q[214]
  PIN q[215]
    DIRECTION OUTPUT ;
    USE SIGNAL ;
    PORT
      LAYER M4 ;
        RECT  14.982 49.68 15.066 49.704 ;
    END
  END q[215]
  PIN q[216]
    DIRECTION OUTPUT ;
    USE SIGNAL ;
    PORT
      LAYER M4 ;
        RECT  14.982 49.92 15.066 49.944 ;
    END
  END q[216]
  PIN q[217]
    DIRECTION OUTPUT ;
    USE SIGNAL ;
    PORT
      LAYER M4 ;
        RECT  14.982 50.112 15.066 50.136 ;
    END
  END q[217]
  PIN q[218]
    DIRECTION OUTPUT ;
    USE SIGNAL ;
    PORT
      LAYER M4 ;
        RECT  14.982 50.304 15.066 50.328 ;
    END
  END q[218]
  PIN q[219]
    DIRECTION OUTPUT ;
    USE SIGNAL ;
    PORT
      LAYER M4 ;
        RECT  14.982 50.544 15.066 50.568 ;
    END
  END q[219]
  PIN q[21]
    DIRECTION OUTPUT ;
    USE SIGNAL ;
    PORT
      LAYER M4 ;
        RECT  14.982 9.696 15.066 9.72 ;
    END
  END q[21]
  PIN q[220]
    DIRECTION OUTPUT ;
    USE SIGNAL ;
    PORT
      LAYER M4 ;
        RECT  14.982 50.736 15.066 50.76 ;
    END
  END q[220]
  PIN q[221]
    DIRECTION OUTPUT ;
    USE SIGNAL ;
    PORT
      LAYER M4 ;
        RECT  14.982 50.928 15.066 50.952 ;
    END
  END q[221]
  PIN q[222]
    DIRECTION OUTPUT ;
    USE SIGNAL ;
    PORT
      LAYER M4 ;
        RECT  14.982 51.12 15.066 51.144 ;
    END
  END q[222]
  PIN q[223]
    DIRECTION OUTPUT ;
    USE SIGNAL ;
    PORT
      LAYER M4 ;
        RECT  14.982 51.36 15.066 51.384 ;
    END
  END q[223]
  PIN q[224]
    DIRECTION OUTPUT ;
    USE SIGNAL ;
    PORT
      LAYER M4 ;
        RECT  14.982 51.552 15.066 51.576 ;
    END
  END q[224]
  PIN q[225]
    DIRECTION OUTPUT ;
    USE SIGNAL ;
    PORT
      LAYER M4 ;
        RECT  14.982 51.744 15.066 51.768 ;
    END
  END q[225]
  PIN q[226]
    DIRECTION OUTPUT ;
    USE SIGNAL ;
    PORT
      LAYER M4 ;
        RECT  14.982 51.984 15.066 52.008 ;
    END
  END q[226]
  PIN q[227]
    DIRECTION OUTPUT ;
    USE SIGNAL ;
    PORT
      LAYER M4 ;
        RECT  14.982 52.176 15.066 52.2 ;
    END
  END q[227]
  PIN q[228]
    DIRECTION OUTPUT ;
    USE SIGNAL ;
    PORT
      LAYER M4 ;
        RECT  14.982 52.368 15.066 52.392 ;
    END
  END q[228]
  PIN q[229]
    DIRECTION OUTPUT ;
    USE SIGNAL ;
    PORT
      LAYER M4 ;
        RECT  14.982 52.608 15.066 52.632 ;
    END
  END q[229]
  PIN q[22]
    DIRECTION OUTPUT ;
    USE SIGNAL ;
    PORT
      LAYER M4 ;
        RECT  14.982 9.936 15.066 9.96 ;
    END
  END q[22]
  PIN q[230]
    DIRECTION OUTPUT ;
    USE SIGNAL ;
    PORT
      LAYER M4 ;
        RECT  14.982 52.8 15.066 52.824 ;
    END
  END q[230]
  PIN q[231]
    DIRECTION OUTPUT ;
    USE SIGNAL ;
    PORT
      LAYER M4 ;
        RECT  14.982 52.992 15.066 53.016 ;
    END
  END q[231]
  PIN q[232]
    DIRECTION OUTPUT ;
    USE SIGNAL ;
    PORT
      LAYER M4 ;
        RECT  14.982 53.184 15.066 53.208 ;
    END
  END q[232]
  PIN q[233]
    DIRECTION OUTPUT ;
    USE SIGNAL ;
    PORT
      LAYER M4 ;
        RECT  14.982 53.424 15.066 53.448 ;
    END
  END q[233]
  PIN q[234]
    DIRECTION OUTPUT ;
    USE SIGNAL ;
    PORT
      LAYER M4 ;
        RECT  14.982 53.616 15.066 53.64 ;
    END
  END q[234]
  PIN q[235]
    DIRECTION OUTPUT ;
    USE SIGNAL ;
    PORT
      LAYER M4 ;
        RECT  14.982 53.808 15.066 53.832 ;
    END
  END q[235]
  PIN q[236]
    DIRECTION OUTPUT ;
    USE SIGNAL ;
    PORT
      LAYER M4 ;
        RECT  14.982 54.048 15.066 54.072 ;
    END
  END q[236]
  PIN q[237]
    DIRECTION OUTPUT ;
    USE SIGNAL ;
    PORT
      LAYER M4 ;
        RECT  14.982 54.24 15.066 54.264 ;
    END
  END q[237]
  PIN q[238]
    DIRECTION OUTPUT ;
    USE SIGNAL ;
    PORT
      LAYER M4 ;
        RECT  14.982 54.432 15.066 54.456 ;
    END
  END q[238]
  PIN q[239]
    DIRECTION OUTPUT ;
    USE SIGNAL ;
    PORT
      LAYER M4 ;
        RECT  14.982 54.624 15.066 54.648 ;
    END
  END q[239]
  PIN q[23]
    DIRECTION OUTPUT ;
    USE SIGNAL ;
    PORT
      LAYER M4 ;
        RECT  14.982 10.128 15.066 10.152 ;
    END
  END q[23]
  PIN q[240]
    DIRECTION OUTPUT ;
    USE SIGNAL ;
    PORT
      LAYER M4 ;
        RECT  14.982 54.864 15.066 54.888 ;
    END
  END q[240]
  PIN q[241]
    DIRECTION OUTPUT ;
    USE SIGNAL ;
    PORT
      LAYER M4 ;
        RECT  14.982 55.056 15.066 55.08 ;
    END
  END q[241]
  PIN q[242]
    DIRECTION OUTPUT ;
    USE SIGNAL ;
    PORT
      LAYER M4 ;
        RECT  14.982 55.248 15.066 55.272 ;
    END
  END q[242]
  PIN q[243]
    DIRECTION OUTPUT ;
    USE SIGNAL ;
    PORT
      LAYER M4 ;
        RECT  14.982 55.488 15.066 55.512 ;
    END
  END q[243]
  PIN q[244]
    DIRECTION OUTPUT ;
    USE SIGNAL ;
    PORT
      LAYER M4 ;
        RECT  14.982 55.68 15.066 55.704 ;
    END
  END q[244]
  PIN q[245]
    DIRECTION OUTPUT ;
    USE SIGNAL ;
    PORT
      LAYER M4 ;
        RECT  14.982 55.872 15.066 55.896 ;
    END
  END q[245]
  PIN q[246]
    DIRECTION OUTPUT ;
    USE SIGNAL ;
    PORT
      LAYER M4 ;
        RECT  14.982 56.112 15.066 56.136 ;
    END
  END q[246]
  PIN q[247]
    DIRECTION OUTPUT ;
    USE SIGNAL ;
    PORT
      LAYER M4 ;
        RECT  14.982 56.304 15.066 56.328 ;
    END
  END q[247]
  PIN q[248]
    DIRECTION OUTPUT ;
    USE SIGNAL ;
    PORT
      LAYER M4 ;
        RECT  14.982 56.496 15.066 56.52 ;
    END
  END q[248]
  PIN q[249]
    DIRECTION OUTPUT ;
    USE SIGNAL ;
    PORT
      LAYER M4 ;
        RECT  14.982 56.688 15.066 56.712 ;
    END
  END q[249]
  PIN q[24]
    DIRECTION OUTPUT ;
    USE SIGNAL ;
    PORT
      LAYER M4 ;
        RECT  14.982 10.32 15.066 10.344 ;
    END
  END q[24]
  PIN q[250]
    DIRECTION OUTPUT ;
    USE SIGNAL ;
    PORT
      LAYER M4 ;
        RECT  14.982 56.928 15.066 56.952 ;
    END
  END q[250]
  PIN q[251]
    DIRECTION OUTPUT ;
    USE SIGNAL ;
    PORT
      LAYER M4 ;
        RECT  14.982 57.12 15.066 57.144 ;
    END
  END q[251]
  PIN q[252]
    DIRECTION OUTPUT ;
    USE SIGNAL ;
    PORT
      LAYER M4 ;
        RECT  14.982 57.312 15.066 57.336 ;
    END
  END q[252]
  PIN q[253]
    DIRECTION OUTPUT ;
    USE SIGNAL ;
    PORT
      LAYER M4 ;
        RECT  14.982 57.552 15.066 57.576 ;
    END
  END q[253]
  PIN q[254]
    DIRECTION OUTPUT ;
    USE SIGNAL ;
    PORT
      LAYER M4 ;
        RECT  14.982 57.744 15.066 57.768 ;
    END
  END q[254]
  PIN q[255]
    DIRECTION OUTPUT ;
    USE SIGNAL ;
    PORT
      LAYER M4 ;
        RECT  14.982 57.936 15.066 57.96 ;
    END
  END q[255]
  PIN q[256]
    DIRECTION OUTPUT ;
    USE SIGNAL ;
    PORT
      LAYER M4 ;
        RECT  14.982 58.128 15.066 58.152 ;
    END
  END q[256]
  PIN q[257]
    DIRECTION OUTPUT ;
    USE SIGNAL ;
    PORT
      LAYER M4 ;
        RECT  14.982 58.368 15.066 58.392 ;
    END
  END q[257]
  PIN q[258]
    DIRECTION OUTPUT ;
    USE SIGNAL ;
    PORT
      LAYER M4 ;
        RECT  14.982 58.56 15.066 58.584 ;
    END
  END q[258]
  PIN q[259]
    DIRECTION OUTPUT ;
    USE SIGNAL ;
    PORT
      LAYER M4 ;
        RECT  14.982 58.752 15.066 58.776 ;
    END
  END q[259]
  PIN q[25]
    DIRECTION OUTPUT ;
    USE SIGNAL ;
    PORT
      LAYER M4 ;
        RECT  14.982 10.56 15.066 10.584 ;
    END
  END q[25]
  PIN q[260]
    DIRECTION OUTPUT ;
    USE SIGNAL ;
    PORT
      LAYER M4 ;
        RECT  14.982 58.992 15.066 59.016 ;
    END
  END q[260]
  PIN q[261]
    DIRECTION OUTPUT ;
    USE SIGNAL ;
    PORT
      LAYER M4 ;
        RECT  14.982 59.184 15.066 59.208 ;
    END
  END q[261]
  PIN q[262]
    DIRECTION OUTPUT ;
    USE SIGNAL ;
    PORT
      LAYER M4 ;
        RECT  14.982 59.376 15.066 59.4 ;
    END
  END q[262]
  PIN q[26]
    DIRECTION OUTPUT ;
    USE SIGNAL ;
    PORT
      LAYER M4 ;
        RECT  14.982 10.752 15.066 10.776 ;
    END
  END q[26]
  PIN q[27]
    DIRECTION OUTPUT ;
    USE SIGNAL ;
    PORT
      LAYER M4 ;
        RECT  14.982 10.944 15.066 10.968 ;
    END
  END q[27]
  PIN q[28]
    DIRECTION OUTPUT ;
    USE SIGNAL ;
    PORT
      LAYER M4 ;
        RECT  14.982 11.136 15.066 11.16 ;
    END
  END q[28]
  PIN q[29]
    DIRECTION OUTPUT ;
    USE SIGNAL ;
    PORT
      LAYER M4 ;
        RECT  14.982 11.376 15.066 11.4 ;
    END
  END q[29]
  PIN q[2]
    DIRECTION OUTPUT ;
    USE SIGNAL ;
    PORT
      LAYER M4 ;
        RECT  14.982 5.808 15.066 5.832 ;
    END
  END q[2]
  PIN q[30]
    DIRECTION OUTPUT ;
    USE SIGNAL ;
    PORT
      LAYER M4 ;
        RECT  14.982 11.568 15.066 11.592 ;
    END
  END q[30]
  PIN q[31]
    DIRECTION OUTPUT ;
    USE SIGNAL ;
    PORT
      LAYER M4 ;
        RECT  14.982 11.76 15.066 11.784 ;
    END
  END q[31]
  PIN q[32]
    DIRECTION OUTPUT ;
    USE SIGNAL ;
    PORT
      LAYER M4 ;
        RECT  14.982 12 15.066 12.024 ;
    END
  END q[32]
  PIN q[33]
    DIRECTION OUTPUT ;
    USE SIGNAL ;
    PORT
      LAYER M4 ;
        RECT  14.982 12.192 15.066 12.216 ;
    END
  END q[33]
  PIN q[34]
    DIRECTION OUTPUT ;
    USE SIGNAL ;
    PORT
      LAYER M4 ;
        RECT  14.982 12.384 15.066 12.408 ;
    END
  END q[34]
  PIN q[35]
    DIRECTION OUTPUT ;
    USE SIGNAL ;
    PORT
      LAYER M4 ;
        RECT  14.982 12.624 15.066 12.648 ;
    END
  END q[35]
  PIN q[36]
    DIRECTION OUTPUT ;
    USE SIGNAL ;
    PORT
      LAYER M4 ;
        RECT  14.982 12.816 15.066 12.84 ;
    END
  END q[36]
  PIN q[37]
    DIRECTION OUTPUT ;
    USE SIGNAL ;
    PORT
      LAYER M4 ;
        RECT  14.982 13.008 15.066 13.032 ;
    END
  END q[37]
  PIN q[38]
    DIRECTION OUTPUT ;
    USE SIGNAL ;
    PORT
      LAYER M4 ;
        RECT  14.982 13.2 15.066 13.224 ;
    END
  END q[38]
  PIN q[39]
    DIRECTION OUTPUT ;
    USE SIGNAL ;
    PORT
      LAYER M4 ;
        RECT  14.982 13.44 15.066 13.464 ;
    END
  END q[39]
  PIN q[3]
    DIRECTION OUTPUT ;
    USE SIGNAL ;
    PORT
      LAYER M4 ;
        RECT  14.982 6 15.066 6.024 ;
    END
  END q[3]
  PIN q[40]
    DIRECTION OUTPUT ;
    USE SIGNAL ;
    PORT
      LAYER M4 ;
        RECT  14.982 13.632 15.066 13.656 ;
    END
  END q[40]
  PIN q[41]
    DIRECTION OUTPUT ;
    USE SIGNAL ;
    PORT
      LAYER M4 ;
        RECT  14.982 13.824 15.066 13.848 ;
    END
  END q[41]
  PIN q[42]
    DIRECTION OUTPUT ;
    USE SIGNAL ;
    PORT
      LAYER M4 ;
        RECT  14.982 14.064 15.066 14.088 ;
    END
  END q[42]
  PIN q[43]
    DIRECTION OUTPUT ;
    USE SIGNAL ;
    PORT
      LAYER M4 ;
        RECT  14.982 14.256 15.066 14.28 ;
    END
  END q[43]
  PIN q[44]
    DIRECTION OUTPUT ;
    USE SIGNAL ;
    PORT
      LAYER M4 ;
        RECT  14.982 14.448 15.066 14.472 ;
    END
  END q[44]
  PIN q[45]
    DIRECTION OUTPUT ;
    USE SIGNAL ;
    PORT
      LAYER M4 ;
        RECT  14.982 14.64 15.066 14.664 ;
    END
  END q[45]
  PIN q[46]
    DIRECTION OUTPUT ;
    USE SIGNAL ;
    PORT
      LAYER M4 ;
        RECT  14.982 14.88 15.066 14.904 ;
    END
  END q[46]
  PIN q[47]
    DIRECTION OUTPUT ;
    USE SIGNAL ;
    PORT
      LAYER M4 ;
        RECT  14.982 15.072 15.066 15.096 ;
    END
  END q[47]
  PIN q[48]
    DIRECTION OUTPUT ;
    USE SIGNAL ;
    PORT
      LAYER M4 ;
        RECT  14.982 15.264 15.066 15.288 ;
    END
  END q[48]
  PIN q[49]
    DIRECTION OUTPUT ;
    USE SIGNAL ;
    PORT
      LAYER M4 ;
        RECT  14.982 15.504 15.066 15.528 ;
    END
  END q[49]
  PIN q[4]
    DIRECTION OUTPUT ;
    USE SIGNAL ;
    PORT
      LAYER M4 ;
        RECT  14.982 6.192 15.066 6.216 ;
    END
  END q[4]
  PIN q[50]
    DIRECTION OUTPUT ;
    USE SIGNAL ;
    PORT
      LAYER M4 ;
        RECT  14.982 15.696 15.066 15.72 ;
    END
  END q[50]
  PIN q[51]
    DIRECTION OUTPUT ;
    USE SIGNAL ;
    PORT
      LAYER M4 ;
        RECT  14.982 15.888 15.066 15.912 ;
    END
  END q[51]
  PIN q[52]
    DIRECTION OUTPUT ;
    USE SIGNAL ;
    PORT
      LAYER M4 ;
        RECT  14.982 16.128 15.066 16.152 ;
    END
  END q[52]
  PIN q[53]
    DIRECTION OUTPUT ;
    USE SIGNAL ;
    PORT
      LAYER M4 ;
        RECT  14.982 16.32 15.066 16.344 ;
    END
  END q[53]
  PIN q[54]
    DIRECTION OUTPUT ;
    USE SIGNAL ;
    PORT
      LAYER M4 ;
        RECT  14.982 16.512 15.066 16.536 ;
    END
  END q[54]
  PIN q[55]
    DIRECTION OUTPUT ;
    USE SIGNAL ;
    PORT
      LAYER M4 ;
        RECT  14.982 16.704 15.066 16.728 ;
    END
  END q[55]
  PIN q[56]
    DIRECTION OUTPUT ;
    USE SIGNAL ;
    PORT
      LAYER M4 ;
        RECT  14.982 16.944 15.066 16.968 ;
    END
  END q[56]
  PIN q[57]
    DIRECTION OUTPUT ;
    USE SIGNAL ;
    PORT
      LAYER M4 ;
        RECT  14.982 17.136 15.066 17.16 ;
    END
  END q[57]
  PIN q[58]
    DIRECTION OUTPUT ;
    USE SIGNAL ;
    PORT
      LAYER M4 ;
        RECT  14.982 17.328 15.066 17.352 ;
    END
  END q[58]
  PIN q[59]
    DIRECTION OUTPUT ;
    USE SIGNAL ;
    PORT
      LAYER M4 ;
        RECT  14.982 17.568 15.066 17.592 ;
    END
  END q[59]
  PIN q[5]
    DIRECTION OUTPUT ;
    USE SIGNAL ;
    PORT
      LAYER M4 ;
        RECT  14.982 6.432 15.066 6.456 ;
    END
  END q[5]
  PIN q[60]
    DIRECTION OUTPUT ;
    USE SIGNAL ;
    PORT
      LAYER M4 ;
        RECT  14.982 17.76 15.066 17.784 ;
    END
  END q[60]
  PIN q[61]
    DIRECTION OUTPUT ;
    USE SIGNAL ;
    PORT
      LAYER M4 ;
        RECT  14.982 17.952 15.066 17.976 ;
    END
  END q[61]
  PIN q[62]
    DIRECTION OUTPUT ;
    USE SIGNAL ;
    PORT
      LAYER M4 ;
        RECT  14.982 18.144 15.066 18.168 ;
    END
  END q[62]
  PIN q[63]
    DIRECTION OUTPUT ;
    USE SIGNAL ;
    PORT
      LAYER M4 ;
        RECT  14.982 18.384 15.066 18.408 ;
    END
  END q[63]
  PIN q[64]
    DIRECTION OUTPUT ;
    USE SIGNAL ;
    PORT
      LAYER M4 ;
        RECT  14.982 18.576 15.066 18.6 ;
    END
  END q[64]
  PIN q[65]
    DIRECTION OUTPUT ;
    USE SIGNAL ;
    PORT
      LAYER M4 ;
        RECT  14.982 18.768 15.066 18.792 ;
    END
  END q[65]
  PIN q[66]
    DIRECTION OUTPUT ;
    USE SIGNAL ;
    PORT
      LAYER M4 ;
        RECT  14.982 19.008 15.066 19.032 ;
    END
  END q[66]
  PIN q[67]
    DIRECTION OUTPUT ;
    USE SIGNAL ;
    PORT
      LAYER M4 ;
        RECT  14.982 19.2 15.066 19.224 ;
    END
  END q[67]
  PIN q[68]
    DIRECTION OUTPUT ;
    USE SIGNAL ;
    PORT
      LAYER M4 ;
        RECT  14.982 19.392 15.066 19.416 ;
    END
  END q[68]
  PIN q[69]
    DIRECTION OUTPUT ;
    USE SIGNAL ;
    PORT
      LAYER M4 ;
        RECT  14.982 19.632 15.066 19.656 ;
    END
  END q[69]
  PIN q[6]
    DIRECTION OUTPUT ;
    USE SIGNAL ;
    PORT
      LAYER M4 ;
        RECT  14.982 6.624 15.066 6.648 ;
    END
  END q[6]
  PIN q[70]
    DIRECTION OUTPUT ;
    USE SIGNAL ;
    PORT
      LAYER M4 ;
        RECT  14.982 19.824 15.066 19.848 ;
    END
  END q[70]
  PIN q[71]
    DIRECTION OUTPUT ;
    USE SIGNAL ;
    PORT
      LAYER M4 ;
        RECT  14.982 20.016 15.066 20.04 ;
    END
  END q[71]
  PIN q[72]
    DIRECTION OUTPUT ;
    USE SIGNAL ;
    PORT
      LAYER M4 ;
        RECT  14.982 20.208 15.066 20.232 ;
    END
  END q[72]
  PIN q[73]
    DIRECTION OUTPUT ;
    USE SIGNAL ;
    PORT
      LAYER M4 ;
        RECT  14.982 20.448 15.066 20.472 ;
    END
  END q[73]
  PIN q[74]
    DIRECTION OUTPUT ;
    USE SIGNAL ;
    PORT
      LAYER M4 ;
        RECT  14.982 20.64 15.066 20.664 ;
    END
  END q[74]
  PIN q[75]
    DIRECTION OUTPUT ;
    USE SIGNAL ;
    PORT
      LAYER M4 ;
        RECT  14.982 20.832 15.066 20.856 ;
    END
  END q[75]
  PIN q[76]
    DIRECTION OUTPUT ;
    USE SIGNAL ;
    PORT
      LAYER M4 ;
        RECT  14.982 21.072 15.066 21.096 ;
    END
  END q[76]
  PIN q[77]
    DIRECTION OUTPUT ;
    USE SIGNAL ;
    PORT
      LAYER M4 ;
        RECT  14.982 21.264 15.066 21.288 ;
    END
  END q[77]
  PIN q[78]
    DIRECTION OUTPUT ;
    USE SIGNAL ;
    PORT
      LAYER M4 ;
        RECT  14.982 21.456 15.066 21.48 ;
    END
  END q[78]
  PIN q[79]
    DIRECTION OUTPUT ;
    USE SIGNAL ;
    PORT
      LAYER M4 ;
        RECT  14.982 21.648 15.066 21.672 ;
    END
  END q[79]
  PIN q[7]
    DIRECTION OUTPUT ;
    USE SIGNAL ;
    PORT
      LAYER M4 ;
        RECT  14.982 6.816 15.066 6.84 ;
    END
  END q[7]
  PIN q[80]
    DIRECTION OUTPUT ;
    USE SIGNAL ;
    PORT
      LAYER M4 ;
        RECT  14.982 21.888 15.066 21.912 ;
    END
  END q[80]
  PIN q[81]
    DIRECTION OUTPUT ;
    USE SIGNAL ;
    PORT
      LAYER M4 ;
        RECT  14.982 22.08 15.066 22.104 ;
    END
  END q[81]
  PIN q[82]
    DIRECTION OUTPUT ;
    USE SIGNAL ;
    PORT
      LAYER M4 ;
        RECT  14.982 22.272 15.066 22.296 ;
    END
  END q[82]
  PIN q[83]
    DIRECTION OUTPUT ;
    USE SIGNAL ;
    PORT
      LAYER M4 ;
        RECT  14.982 22.512 15.066 22.536 ;
    END
  END q[83]
  PIN q[84]
    DIRECTION OUTPUT ;
    USE SIGNAL ;
    PORT
      LAYER M4 ;
        RECT  14.982 22.704 15.066 22.728 ;
    END
  END q[84]
  PIN q[85]
    DIRECTION OUTPUT ;
    USE SIGNAL ;
    PORT
      LAYER M4 ;
        RECT  14.982 22.896 15.066 22.92 ;
    END
  END q[85]
  PIN q[86]
    DIRECTION OUTPUT ;
    USE SIGNAL ;
    PORT
      LAYER M4 ;
        RECT  14.982 23.136 15.066 23.16 ;
    END
  END q[86]
  PIN q[87]
    DIRECTION OUTPUT ;
    USE SIGNAL ;
    PORT
      LAYER M4 ;
        RECT  14.982 23.328 15.066 23.352 ;
    END
  END q[87]
  PIN q[88]
    DIRECTION OUTPUT ;
    USE SIGNAL ;
    PORT
      LAYER M4 ;
        RECT  14.982 23.52 15.066 23.544 ;
    END
  END q[88]
  PIN q[89]
    DIRECTION OUTPUT ;
    USE SIGNAL ;
    PORT
      LAYER M4 ;
        RECT  14.982 23.712 15.066 23.736 ;
    END
  END q[89]
  PIN q[8]
    DIRECTION OUTPUT ;
    USE SIGNAL ;
    PORT
      LAYER M4 ;
        RECT  14.982 7.056 15.066 7.08 ;
    END
  END q[8]
  PIN q[90]
    DIRECTION OUTPUT ;
    USE SIGNAL ;
    PORT
      LAYER M4 ;
        RECT  14.982 23.952 15.066 23.976 ;
    END
  END q[90]
  PIN q[91]
    DIRECTION OUTPUT ;
    USE SIGNAL ;
    PORT
      LAYER M4 ;
        RECT  14.982 24.144 15.066 24.168 ;
    END
  END q[91]
  PIN q[92]
    DIRECTION OUTPUT ;
    USE SIGNAL ;
    PORT
      LAYER M4 ;
        RECT  14.982 24.336 15.066 24.36 ;
    END
  END q[92]
  PIN q[93]
    DIRECTION OUTPUT ;
    USE SIGNAL ;
    PORT
      LAYER M4 ;
        RECT  14.982 24.576 15.066 24.6 ;
    END
  END q[93]
  PIN q[94]
    DIRECTION OUTPUT ;
    USE SIGNAL ;
    PORT
      LAYER M4 ;
        RECT  14.982 24.768 15.066 24.792 ;
    END
  END q[94]
  PIN q[95]
    DIRECTION OUTPUT ;
    USE SIGNAL ;
    PORT
      LAYER M4 ;
        RECT  14.982 24.96 15.066 24.984 ;
    END
  END q[95]
  PIN q[96]
    DIRECTION OUTPUT ;
    USE SIGNAL ;
    PORT
      LAYER M4 ;
        RECT  14.982 25.152 15.066 25.176 ;
    END
  END q[96]
  PIN q[97]
    DIRECTION OUTPUT ;
    USE SIGNAL ;
    PORT
      LAYER M4 ;
        RECT  14.982 25.392 15.066 25.416 ;
    END
  END q[97]
  PIN q[98]
    DIRECTION OUTPUT ;
    USE SIGNAL ;
    PORT
      LAYER M4 ;
        RECT  14.982 25.584 15.066 25.608 ;
    END
  END q[98]
  PIN q[99]
    DIRECTION OUTPUT ;
    USE SIGNAL ;
    PORT
      LAYER M4 ;
        RECT  14.982 25.776 15.066 25.8 ;
    END
  END q[99]
  PIN q[9]
    DIRECTION OUTPUT ;
    USE SIGNAL ;
    PORT
      LAYER M4 ;
        RECT  14.982 7.248 15.066 7.272 ;
    END
  END q[9]
  PIN rst_n
    DIRECTION INPUT ;
    USE SIGNAL ;
    PORT
      LAYER M5 ;
        RECT  9.696 0.054 9.72 0.138 ;
    END
    PORT
      LAYER M5 ;
        RECT  9.696 0.08 9.72 2.137 ;
    END
  END rst_n
  PIN VDD
    DIRECTION INOUT ;
    USE POWER ;
    PORT
      LAYER M5 ;
        RECT  10.692 2.151 10.812 62.649 ;
        RECT  7.992 2.151 8.112 62.649 ;
        RECT  5.292 2.151 5.412 62.649 ;
        RECT  2.592 2.151 2.712 62.649 ;
    END
  END VDD
  PIN VSS
    DIRECTION INOUT ;
    USE GROUND ;
    PORT
      LAYER M5 ;
        RECT  10.5 2.137 10.62 62.663 ;
        RECT  7.8 2.137 7.92 62.663 ;
        RECT  5.1 2.137 5.22 62.663 ;
        RECT  2.4 2.137 2.52 62.663 ;
    END
  END VSS
  # OT_OBS_CLOSED layer=M5 d_um=1.536 added=27
  OBS
    LAYER RVTN ;
     RECT  2.16 2.16 12.96 2.295 ;
     RECT  2.16 2.565 12.96 2.835 ;
     RECT  2.16 3.105 12.96 3.375 ;
     RECT  2.16 3.645 12.96 3.915 ;
     RECT  2.16 4.185 12.96 4.455 ;
     RECT  2.16 4.725 12.96 4.995 ;
     RECT  2.16 5.265 12.96 5.535 ;
     RECT  2.16 5.805 12.96 6.075 ;
     RECT  2.16 6.345 12.96 6.615 ;
     RECT  2.16 6.885 12.96 7.155 ;
     RECT  2.16 7.425 12.96 7.695 ;
     RECT  2.16 7.965 12.96 8.235 ;
     RECT  2.16 8.505 12.96 8.775 ;
     RECT  2.16 9.045 12.96 9.315 ;
     RECT  2.16 9.585 12.96 9.855 ;
     RECT  2.16 10.125 12.96 10.395 ;
     RECT  2.16 10.665 12.96 10.935 ;
     RECT  2.16 11.205 12.96 11.475 ;
     RECT  2.16 11.745 12.96 12.015 ;
     RECT  2.16 12.285 12.96 12.555 ;
     RECT  2.16 12.825 12.96 13.095 ;
     RECT  2.16 13.365 12.96 13.635 ;
     RECT  2.16 13.905 12.96 14.175 ;
     RECT  2.16 14.445 12.96 14.715 ;
     RECT  2.16 14.985 12.96 15.255 ;
     RECT  2.16 15.525 12.96 15.795 ;
     RECT  2.16 16.065 12.96 16.335 ;
     RECT  2.16 16.605 12.96 16.875 ;
     RECT  2.16 17.145 12.96 17.415 ;
     RECT  2.16 17.685 12.96 17.955 ;
     RECT  2.16 18.225 12.96 18.495 ;
     RECT  2.16 18.765 12.96 19.035 ;
     RECT  2.16 19.305 12.96 19.575 ;
     RECT  2.16 19.845 12.96 20.115 ;
     RECT  2.16 20.385 12.96 20.655 ;
     RECT  2.16 20.925 12.96 21.195 ;
     RECT  2.16 21.465 12.96 21.735 ;
     RECT  2.16 22.005 12.96 22.275 ;
     RECT  2.16 22.545 12.96 22.815 ;
     RECT  2.16 23.085 12.96 23.355 ;
     RECT  2.16 23.625 12.96 23.895 ;
     RECT  2.16 24.165 12.96 24.435 ;
     RECT  2.16 24.705 12.96 24.975 ;
     RECT  2.16 25.245 12.96 25.515 ;
     RECT  2.16 25.785 12.96 26.055 ;
     RECT  2.16 26.325 12.96 26.595 ;
     RECT  2.16 26.865 12.96 27.135 ;
     RECT  2.16 27.405 12.96 27.675 ;
     RECT  2.16 27.945 12.96 28.215 ;
     RECT  2.16 28.485 12.96 28.755 ;
     RECT  2.16 29.025 12.96 29.295 ;
     RECT  2.16 29.565 12.96 29.835 ;
     RECT  2.16 30.105 12.96 30.375 ;
     RECT  2.16 30.645 12.96 30.915 ;
     RECT  2.16 31.185 12.96 31.455 ;
     RECT  2.16 31.725 12.96 31.995 ;
     RECT  2.16 32.265 12.96 32.535 ;
     RECT  2.16 32.805 12.96 33.075 ;
     RECT  2.16 33.345 12.96 33.615 ;
     RECT  2.16 33.885 12.96 34.155 ;
     RECT  2.16 34.425 12.96 34.695 ;
     RECT  2.16 34.965 12.96 35.235 ;
     RECT  2.16 35.505 12.96 35.775 ;
     RECT  2.16 36.045 12.96 36.315 ;
     RECT  2.16 36.585 12.96 36.855 ;
     RECT  2.16 37.125 12.96 37.395 ;
     RECT  2.16 37.665 12.96 37.935 ;
     RECT  2.16 38.205 12.96 38.475 ;
     RECT  2.16 38.745 12.96 39.015 ;
     RECT  2.16 39.285 12.96 39.555 ;
     RECT  2.16 39.825 12.96 40.095 ;
     RECT  2.16 40.365 12.96 40.635 ;
     RECT  2.16 40.905 12.96 41.175 ;
     RECT  2.16 41.445 12.96 41.715 ;
     RECT  2.16 41.985 12.96 42.255 ;
     RECT  2.16 42.525 12.96 42.795 ;
     RECT  2.16 43.065 12.96 43.335 ;
     RECT  2.16 43.605 12.96 43.875 ;
     RECT  2.16 44.145 12.96 44.415 ;
     RECT  2.16 44.685 12.96 44.955 ;
     RECT  2.16 45.225 12.96 45.495 ;
     RECT  2.16 45.765 12.96 46.035 ;
     RECT  2.16 46.305 12.96 46.575 ;
     RECT  2.16 46.845 12.96 47.115 ;
     RECT  2.16 47.385 12.96 47.655 ;
     RECT  2.16 47.925 12.96 48.195 ;
     RECT  2.16 48.465 12.96 48.735 ;
     RECT  2.16 49.005 12.96 49.275 ;
     RECT  2.16 49.545 12.96 49.815 ;
     RECT  2.16 50.085 12.96 50.355 ;
     RECT  2.16 50.625 12.96 50.895 ;
     RECT  2.16 51.165 12.96 51.435 ;
     RECT  2.16 51.705 12.96 51.975 ;
     RECT  2.16 52.245 12.96 52.515 ;
     RECT  2.16 52.785 12.96 53.055 ;
     RECT  2.16 53.325 12.96 53.595 ;
     RECT  2.16 53.865 12.96 54.135 ;
     RECT  2.16 54.405 12.96 54.675 ;
     RECT  2.16 54.945 12.96 55.215 ;
     RECT  2.16 55.485 12.96 55.755 ;
     RECT  2.16 56.025 12.96 56.295 ;
     RECT  2.16 56.565 12.96 56.835 ;
     RECT  2.16 57.105 12.96 57.375 ;
     RECT  2.16 57.645 12.96 57.915 ;
     RECT  2.16 58.185 12.96 58.455 ;
     RECT  2.16 58.725 12.96 58.995 ;
     RECT  2.16 59.265 12.96 59.535 ;
     RECT  2.16 59.805 12.96 60.075 ;
     RECT  2.16 60.345 12.96 60.615 ;
     RECT  2.16 60.885 12.96 61.155 ;
     RECT  2.16 61.425 12.96 61.695 ;
     RECT  2.16 61.965 12.96 62.235 ;
     RECT  2.16 62.505 12.96 62.64 ;
    LAYER RVTP ;
     RECT  2.16 2.295 12.96 2.565 ;
     RECT  2.16 2.835 12.96 3.105 ;
     RECT  2.16 3.375 12.96 3.645 ;
     RECT  2.16 3.915 12.96 4.185 ;
     RECT  2.16 4.455 12.96 4.725 ;
     RECT  2.16 4.995 12.96 5.265 ;
     RECT  2.16 5.535 12.96 5.805 ;
     RECT  2.16 6.075 12.96 6.345 ;
     RECT  2.16 6.615 12.96 6.885 ;
     RECT  2.16 7.155 12.96 7.425 ;
     RECT  2.16 7.695 12.96 7.965 ;
     RECT  2.16 8.235 12.96 8.505 ;
     RECT  2.16 8.775 12.96 9.045 ;
     RECT  2.16 9.315 12.96 9.585 ;
     RECT  2.16 9.855 12.96 10.125 ;
     RECT  2.16 10.395 12.96 10.665 ;
     RECT  2.16 10.935 12.96 11.205 ;
     RECT  2.16 11.475 12.96 11.745 ;
     RECT  2.16 12.015 12.96 12.285 ;
     RECT  2.16 12.555 12.96 12.825 ;
     RECT  2.16 13.095 12.96 13.365 ;
     RECT  2.16 13.635 12.96 13.905 ;
     RECT  2.16 14.175 12.96 14.445 ;
     RECT  2.16 14.715 12.96 14.985 ;
     RECT  2.16 15.255 12.96 15.525 ;
     RECT  2.16 15.795 12.96 16.065 ;
     RECT  2.16 16.335 12.96 16.605 ;
     RECT  2.16 16.875 12.96 17.145 ;
     RECT  2.16 17.415 12.96 17.685 ;
     RECT  2.16 17.955 12.96 18.225 ;
     RECT  2.16 18.495 12.96 18.765 ;
     RECT  2.16 19.035 12.96 19.305 ;
     RECT  2.16 19.575 12.96 19.845 ;
     RECT  2.16 20.115 12.96 20.385 ;
     RECT  2.16 20.655 12.96 20.925 ;
     RECT  2.16 21.195 12.96 21.465 ;
     RECT  2.16 21.735 12.96 22.005 ;
     RECT  2.16 22.275 12.96 22.545 ;
     RECT  2.16 22.815 12.96 23.085 ;
     RECT  2.16 23.355 12.96 23.625 ;
     RECT  2.16 23.895 12.96 24.165 ;
     RECT  2.16 24.435 12.96 24.705 ;
     RECT  2.16 24.975 12.96 25.245 ;
     RECT  2.16 25.515 12.96 25.785 ;
     RECT  2.16 26.055 12.96 26.325 ;
     RECT  2.16 26.595 12.96 26.865 ;
     RECT  2.16 27.135 12.96 27.405 ;
     RECT  2.16 27.675 12.96 27.945 ;
     RECT  2.16 28.215 12.96 28.485 ;
     RECT  2.16 28.755 12.96 29.025 ;
     RECT  2.16 29.295 12.96 29.565 ;
     RECT  2.16 29.835 12.96 30.105 ;
     RECT  2.16 30.375 12.96 30.645 ;
     RECT  2.16 30.915 12.96 31.185 ;
     RECT  2.16 31.455 12.96 31.725 ;
     RECT  2.16 31.995 12.96 32.265 ;
     RECT  2.16 32.535 12.96 32.805 ;
     RECT  2.16 33.075 12.96 33.345 ;
     RECT  2.16 33.615 12.96 33.885 ;
     RECT  2.16 34.155 12.96 34.425 ;
     RECT  2.16 34.695 12.96 34.965 ;
     RECT  2.16 35.235 12.96 35.505 ;
     RECT  2.16 35.775 12.96 36.045 ;
     RECT  2.16 36.315 12.96 36.585 ;
     RECT  2.16 36.855 12.96 37.125 ;
     RECT  2.16 37.395 12.96 37.665 ;
     RECT  2.16 37.935 12.96 38.205 ;
     RECT  2.16 38.475 12.96 38.745 ;
     RECT  2.16 39.015 12.96 39.285 ;
     RECT  2.16 39.555 12.96 39.825 ;
     RECT  2.16 40.095 12.96 40.365 ;
     RECT  2.16 40.635 12.96 40.905 ;
     RECT  2.16 41.175 12.96 41.445 ;
     RECT  2.16 41.715 12.96 41.985 ;
     RECT  2.16 42.255 12.96 42.525 ;
     RECT  2.16 42.795 12.96 43.065 ;
     RECT  2.16 43.335 12.96 43.605 ;
     RECT  2.16 43.875 12.96 44.145 ;
     RECT  2.16 44.415 12.96 44.685 ;
     RECT  2.16 44.955 12.96 45.225 ;
     RECT  2.16 45.495 12.96 45.765 ;
     RECT  2.16 46.035 12.96 46.305 ;
     RECT  2.16 46.575 12.96 46.845 ;
     RECT  2.16 47.115 12.96 47.385 ;
     RECT  2.16 47.655 12.96 47.925 ;
     RECT  2.16 48.195 12.96 48.465 ;
     RECT  2.16 48.735 12.96 49.005 ;
     RECT  2.16 49.275 12.96 49.545 ;
     RECT  2.16 49.815 12.96 50.085 ;
     RECT  2.16 50.355 12.96 50.625 ;
     RECT  2.16 50.895 12.96 51.165 ;
     RECT  2.16 51.435 12.96 51.705 ;
     RECT  2.16 51.975 12.96 52.245 ;
     RECT  2.16 52.515 12.96 52.785 ;
     RECT  2.16 53.055 12.96 53.325 ;
     RECT  2.16 53.595 12.96 53.865 ;
     RECT  2.16 54.135 12.96 54.405 ;
     RECT  2.16 54.675 12.96 54.945 ;
     RECT  2.16 55.215 12.96 55.485 ;
     RECT  2.16 55.755 12.96 56.025 ;
     RECT  2.16 56.295 12.96 56.565 ;
     RECT  2.16 56.835 12.96 57.105 ;
     RECT  2.16 57.375 12.96 57.645 ;
     RECT  2.16 57.915 12.96 58.185 ;
     RECT  2.16 58.455 12.96 58.725 ;
     RECT  2.16 58.995 12.96 59.265 ;
     RECT  2.16 59.535 12.96 59.805 ;
     RECT  2.16 60.075 12.96 60.345 ;
     RECT  2.16 60.615 12.96 60.885 ;
     RECT  2.16 61.155 12.96 61.425 ;
     RECT  2.16 61.695 12.96 61.965 ;
     RECT  2.16 62.235 12.96 62.505 ;
    LAYER M1 ;
     RECT  2.16 2.151 12.96 62.649 ;
    LAYER M2 ;
     RECT  0.139 4.77 0.175 4.788 ;
     RECT  0.139 5.85 0.175 5.868 ;
     RECT  0.175 4.77 2.16 5.868 ;
     RECT  0.175 6.822 2.16 6.84 ;
     RECT  0.139 11.952 2.16 11.97 ;
     RECT  0.139 17.622 2.16 17.64 ;
     RECT  0.535 22.086 2.16 22.104 ;
     RECT  0.535 27.216 2.16 27.234 ;
     RECT  0.535 28.962 2.16 28.98 ;
     RECT  0.535 33.588 2.16 33.606 ;
     RECT  2.16 2.151 12.96 62.649 ;
     RECT  12.96 4.806 13.667 59.184 ;
     RECT  13.667 4.806 13.703 22.806 ;
     RECT  13.667 43.848 13.703 47.034 ;
     RECT  13.703 12.528 13.739 22.734 ;
     RECT  13.739 12.528 14.207 20.844 ;
     RECT  13.667 23.706 14.207 31.914 ;
     RECT  13.667 54.612 14.207 59.184 ;
     RECT  13.703 4.806 14.243 8.964 ;
     RECT  13.703 9.936 14.243 11.664 ;
     RECT  14.207 12.528 14.243 13.284 ;
     RECT  14.207 14.346 14.243 20.844 ;
     RECT  13.739 22.086 14.243 22.734 ;
     RECT  14.207 23.706 14.243 30.834 ;
     RECT  14.207 31.626 14.243 31.914 ;
     RECT  13.667 32.886 14.243 42.75 ;
     RECT  13.703 43.848 14.243 45.954 ;
     RECT  13.703 46.746 14.243 47.034 ;
     RECT  13.667 47.826 14.243 53.784 ;
     RECT  14.207 54.612 14.243 58.914 ;
     RECT  12.96 60.246 14.243 60.804 ;
     RECT  14.243 6.696 14.279 6.714 ;
     RECT  14.243 10.404 14.279 10.422 ;
     RECT  14.243 11.214 14.279 11.304 ;
     RECT  14.243 12.528 14.279 13.014 ;
     RECT  14.243 17.496 14.279 17.676 ;
     RECT  14.243 20.826 14.279 20.844 ;
     RECT  14.243 23.706 14.279 23.724 ;
     RECT  14.243 25.794 14.279 26.154 ;
     RECT  14.243 30.186 14.279 30.474 ;
     RECT  14.243 35.406 14.279 36.414 ;
     RECT  14.243 37.206 14.279 37.62 ;
     RECT  14.243 51.174 14.279 51.192 ;
     RECT  14.243 53.334 14.279 53.694 ;
     RECT  14.243 16.506 14.315 16.524 ;
     RECT  14.279 30.186 14.315 30.204 ;
     RECT  14.279 37.602 14.315 37.62 ;
     RECT  14.279 53.676 14.315 53.694 ;
     RECT  14.243 32.886 14.891 33.984 ;
     RECT  14.243 4.806 14.927 5.634 ;
     RECT  14.891 32.886 14.927 33.606 ;
     RECT  14.243 60.516 14.927 60.804 ;
     RECT  14.927 4.806 14.963 4.824 ;
     RECT  14.927 5.616 14.963 5.634 ;
     RECT  14.243 7.938 14.963 7.956 ;
     RECT  14.279 12.528 14.963 12.546 ;
     RECT  14.279 17.658 14.963 17.676 ;
     RECT  14.243 19.008 14.963 19.026 ;
     RECT  14.243 22.212 14.963 22.23 ;
     RECT  14.243 27.216 14.963 27.234 ;
     RECT  14.243 31.896 14.963 31.914 ;
     RECT  14.927 32.886 14.963 32.904 ;
     RECT  14.279 35.406 14.963 35.424 ;
     RECT  14.243 38.646 14.963 39.312 ;
     RECT  14.243 41.256 14.963 41.274 ;
     RECT  14.243 42.732 14.963 42.75 ;
     RECT  14.243 43.848 14.963 44.334 ;
     RECT  14.243 48.438 14.963 48.456 ;
     RECT  14.243 55.296 14.963 55.314 ;
     RECT  14.243 58.122 14.963 58.14 ;
     RECT  14.927 60.516 14.963 60.534 ;
    LAYER M3 ;
     RECT  2.415 2.143 2.505 2.413 ;
     RECT  5.115 2.143 5.205 2.413 ;
     RECT  7.815 2.143 7.905 2.413 ;
     RECT  10.515 2.143 10.605 2.413 ;
     RECT  5.115 2.413 5.397 4.351 ;
     RECT  10.515 2.413 10.797 4.801 ;
     RECT  11.952 4.531 12.618 4.801 ;
     RECT  2.415 2.413 2.697 5.035 ;
     RECT  5.115 4.351 5.526 5.071 ;
     RECT  14.94 4.801 14.958 5.071 ;
     RECT  0.144 4.765 0.162 5.233 ;
     RECT  5.115 5.071 6.138 5.269 ;
     RECT  2.415 5.035 3.402 5.305 ;
     RECT  4.824 5.269 6.138 5.341 ;
     RECT  10.515 4.801 12.618 5.341 ;
     RECT  4.536 5.341 6.282 5.539 ;
     RECT  2.376 5.305 3.402 5.575 ;
     RECT  4.176 5.539 6.282 5.575 ;
     RECT  7.815 2.413 8.097 5.611 ;
     RECT  14.904 5.071 14.958 5.803 ;
     RECT  0.144 5.233 0.198 5.837 ;
     RECT  2.376 5.575 6.282 5.845 ;
     RECT  7.815 5.611 8.298 5.845 ;
     RECT  14.22 5.803 14.958 5.881 ;
     RECT  14.184 5.881 14.958 6.029 ;
     RECT  2.376 5.845 8.298 6.079 ;
     RECT  2.376 6.079 8.586 6.115 ;
     RECT  10.26 5.341 12.834 6.151 ;
     RECT  10.26 6.151 13.122 6.221 ;
     RECT  2.34 6.115 8.946 6.385 ;
     RECT  10.26 6.221 12.834 6.461 ;
     RECT  10.26 6.461 12.654 6.539 ;
     RECT  14.256 6.029 14.958 6.653 ;
     RECT  10.26 6.539 10.89 6.691 ;
     RECT  14.256 6.653 14.274 6.808 ;
     RECT  0.144 5.837 0.162 6.817 ;
     RECT  0.144 6.817 0.198 6.845 ;
     RECT  0.18 6.845 0.198 7.085 ;
     RECT  14.22 6.808 14.274 7.085 ;
     RECT  11.628 6.539 12.654 7.115 ;
     RECT  2.304 6.385 8.946 7.159 ;
     RECT  9.684 6.691 10.89 7.159 ;
     RECT  14.22 7.085 14.238 7.231 ;
     RECT  2.304 7.159 10.89 7.321 ;
     RECT  11.628 7.115 12.474 7.321 ;
     RECT  14.184 7.231 14.238 7.771 ;
     RECT  2.304 7.321 12.474 7.861 ;
     RECT  2.304 7.861 12.618 7.889 ;
     RECT  13.536 7.771 14.238 7.901 ;
     RECT  7.2 7.889 8.946 7.925 ;
     RECT  14.184 7.901 14.238 7.933 ;
     RECT  14.184 7.933 14.958 8.285 ;
     RECT  2.304 7.889 6.426 8.779 ;
     RECT  7.2 7.925 8.874 8.779 ;
     RECT  9.9 7.889 12.618 8.807 ;
     RECT  2.304 8.779 8.874 8.815 ;
     RECT  2.304 8.815 8.946 8.969 ;
     RECT  14.184 8.285 14.238 8.969 ;
     RECT  13.644 9.115 13.698 9.307 ;
     RECT  13.536 9.307 13.698 9.499 ;
     RECT  13.068 9.499 13.698 9.617 ;
     RECT  9.9 8.807 12.186 9.661 ;
     RECT  13.68 9.617 13.698 9.725 ;
     RECT  0.144 9.691 0.162 9.821 ;
     RECT  14.22 9.931 14.238 10.123 ;
     RECT  2.304 8.969 8.91 10.435 ;
     RECT  2.304 10.435 8.946 10.471 ;
     RECT  9.9 9.661 12.618 10.471 ;
     RECT  14.22 10.123 14.274 10.555 ;
     RECT  0.144 10.555 0.162 10.685 ;
     RECT  2.304 10.471 12.618 10.741 ;
     RECT  13.608 10.555 14.274 10.967 ;
     RECT  2.304 10.741 12.834 11.129 ;
     RECT  2.304 11.129 12.618 11.435 ;
     RECT  2.415 11.435 12.618 11.939 ;
     RECT  0.144 11.563 0.162 12.029 ;
     RECT  2.415 11.939 12.222 12.187 ;
     RECT  2.304 12.187 12.222 12.269 ;
     RECT  13.644 10.967 14.274 12.523 ;
     RECT  8.856 12.269 12.222 12.551 ;
     RECT  13.644 12.523 14.958 12.653 ;
     RECT  9.9 12.551 12.222 12.865 ;
     RECT  13.644 12.653 14.274 13.091 ;
     RECT  2.304 12.269 8.097 13.325 ;
     RECT  9.9 12.865 12.654 13.441 ;
     RECT  14.22 13.091 14.274 13.469 ;
     RECT  2.415 13.325 8.097 13.531 ;
     RECT  8.856 12.551 8.91 13.531 ;
     RECT  9.648 13.441 12.654 13.559 ;
     RECT  0.216 13.435 0.234 13.613 ;
     RECT  2.415 13.531 8.91 13.675 ;
     RECT  14.22 13.469 14.238 13.819 ;
     RECT  2.415 13.675 8.946 13.829 ;
     RECT  2.415 13.829 8.91 13.865 ;
     RECT  2.415 13.865 3.402 14.059 ;
     RECT  9.864 13.559 12.618 14.093 ;
     RECT  2.304 14.059 3.402 14.099 ;
     RECT  14.184 13.819 14.238 14.251 ;
     RECT  13.536 14.251 14.238 14.441 ;
     RECT  9.864 14.093 12.582 14.675 ;
     RECT  4.176 13.865 8.91 14.755 ;
     RECT  13.644 14.441 14.238 14.909 ;
     RECT  2.304 14.099 3.366 15.025 ;
     RECT  4.104 14.755 8.91 15.025 ;
     RECT  2.304 15.025 8.91 15.295 ;
     RECT  9.864 14.675 12.15 15.331 ;
     RECT  9.684 15.331 12.15 15.421 ;
     RECT  2.304 15.295 8.946 15.449 ;
     RECT  9.684 15.421 12.33 15.485 ;
     RECT  9.864 15.485 12.33 15.719 ;
     RECT  13.068 15.601 13.086 15.725 ;
     RECT  12.204 15.719 12.33 16.105 ;
     RECT  2.304 15.449 8.91 16.123 ;
     RECT  2.268 16.123 8.91 16.295 ;
     RECT  14.22 14.909 14.238 16.303 ;
     RECT  2.304 16.295 8.91 16.411 ;
     RECT  9.864 15.719 11.322 16.501 ;
     RECT  12.204 16.105 12.546 16.501 ;
     RECT  14.184 16.303 14.238 16.501 ;
     RECT  2.304 16.411 9.126 16.573 ;
     RECT  9.864 16.501 12.546 16.573 ;
     RECT  14.184 16.501 14.31 16.733 ;
     RECT  14.184 16.733 14.274 16.939 ;
     RECT  13.644 16.939 14.274 16.979 ;
     RECT  2.304 16.573 12.546 17.323 ;
     RECT  14.22 16.979 14.274 17.653 ;
     RECT  14.22 17.653 14.958 17.789 ;
     RECT  14.22 17.789 14.238 17.923 ;
     RECT  13.68 17.923 14.238 18.139 ;
     RECT  2.304 17.323 12.618 18.149 ;
     RECT  13.644 18.139 14.238 18.413 ;
     RECT  2.304 18.149 12.582 18.419 ;
     RECT  0.144 17.617 0.162 18.509 ;
     RECT  14.22 18.413 14.238 18.571 ;
     RECT  12.528 18.419 12.582 18.931 ;
     RECT  14.22 18.571 14.958 19.031 ;
     RECT  12.528 18.931 13.086 19.037 ;
     RECT  2.304 18.419 11.682 19.201 ;
     RECT  12.528 19.037 12.582 19.201 ;
     RECT  2.304 19.201 12.582 19.301 ;
     RECT  14.22 19.031 14.238 19.387 ;
     RECT  2.304 19.301 8.802 20.155 ;
     RECT  2.304 20.155 8.838 20.309 ;
     RECT  9.864 19.301 12.582 20.425 ;
     RECT  2.304 20.309 8.802 20.443 ;
     RECT  13.608 19.387 14.238 20.443 ;
     RECT  2.268 20.443 8.802 20.687 ;
     RECT  13.536 20.443 14.238 20.821 ;
     RECT  13.536 20.821 14.274 20.921 ;
     RECT  9.864 20.425 12.654 21.001 ;
     RECT  9.54 21.001 12.654 21.119 ;
     RECT  9.54 21.119 12.582 21.155 ;
     RECT  13.644 20.921 14.274 21.485 ;
     RECT  9.972 21.155 12.582 21.569 ;
     RECT  2.304 20.687 8.802 21.775 ;
     RECT  2.304 21.775 8.838 21.901 ;
     RECT  0.216 21.259 0.234 21.979 ;
     RECT  13.644 21.485 14.238 22.001 ;
     RECT  12.06 21.569 12.582 22.045 ;
     RECT  0.144 21.979 0.234 22.081 ;
     RECT  2.304 21.901 9.09 22.081 ;
     RECT  0.144 22.081 0.558 22.109 ;
     RECT  2.304 22.081 9.162 22.199 ;
     RECT  14.184 22.001 14.238 22.207 ;
     RECT  0.54 22.109 0.558 22.301 ;
     RECT  14.184 22.207 14.958 22.301 ;
     RECT  9.972 21.569 11.142 22.477 ;
     RECT  12.06 22.045 12.654 22.477 ;
     RECT  2.304 22.199 8.802 22.505 ;
     RECT  9.972 22.477 12.654 22.621 ;
     RECT  14.184 22.301 14.238 22.739 ;
     RECT  9.792 22.621 12.654 23.009 ;
     RECT  13.68 22.783 13.698 23.125 ;
     RECT  2.304 22.505 5.814 23.251 ;
     RECT  6.552 22.505 8.802 23.251 ;
     RECT  13.644 23.125 13.698 23.357 ;
     RECT  2.304 23.251 8.802 23.395 ;
     RECT  9.792 23.009 12.51 23.431 ;
     RECT  14.184 23.515 14.238 23.701 ;
     RECT  9.648 23.431 12.51 23.791 ;
     RECT  0.144 23.707 0.162 23.885 ;
     RECT  9.648 23.791 12.546 23.971 ;
     RECT  14.184 23.701 14.274 23.981 ;
     RECT  2.304 23.395 8.838 24.241 ;
     RECT  9.576 23.971 12.546 24.241 ;
     RECT  2.304 24.241 12.546 24.331 ;
     RECT  14.184 23.981 14.238 24.331 ;
     RECT  2.304 24.331 12.762 24.395 ;
     RECT  9.864 24.395 12.762 24.763 ;
     RECT  13.644 24.331 14.238 24.763 ;
     RECT  9.864 24.763 14.238 24.809 ;
     RECT  9.864 24.809 12.654 24.899 ;
     RECT  13.644 24.809 14.238 24.989 ;
     RECT  2.304 24.395 8.838 25.169 ;
     RECT  9.972 24.899 12.654 25.169 ;
     RECT  0.144 25.387 0.162 25.517 ;
     RECT  14.184 24.989 14.238 25.579 ;
     RECT  9.972 25.169 12.618 25.753 ;
     RECT  9.576 25.753 12.618 25.979 ;
     RECT  14.184 25.579 14.274 26.011 ;
     RECT  12.6 25.979 12.618 26.321 ;
     RECT  9.972 25.979 11.718 26.519 ;
     RECT  13.644 26.011 14.274 26.519 ;
     RECT  13.68 26.519 14.274 26.635 ;
     RECT  2.304 25.169 8.802 26.797 ;
     RECT  13.68 26.635 14.958 27.239 ;
     RECT  12.384 27.031 12.402 27.301 ;
     RECT  9.972 26.519 11.538 27.337 ;
     RECT  12.384 27.301 12.51 27.337 ;
     RECT  9.972 27.337 12.51 27.409 ;
     RECT  13.68 27.239 14.238 27.409 ;
     RECT  0.54 27.211 0.558 27.485 ;
     RECT  9.972 27.409 14.238 27.485 ;
     RECT  9.972 27.485 12.69 27.571 ;
     RECT  2.304 26.797 8.91 27.715 ;
     RECT  13.644 27.485 14.238 27.869 ;
     RECT  9.936 27.571 12.69 27.905 ;
     RECT  2.304 27.715 8.946 28.075 ;
     RECT  10.224 27.905 12.69 28.255 ;
     RECT  2.268 28.075 8.946 28.283 ;
     RECT  10.224 28.255 13.086 28.301 ;
     RECT  2.304 28.283 8.946 28.561 ;
     RECT  2.304 28.561 9.162 28.651 ;
     RECT  10.224 28.301 12.618 28.651 ;
     RECT  14.22 27.869 14.238 28.651 ;
     RECT  2.304 28.651 12.618 28.715 ;
     RECT  13.644 28.651 14.238 28.751 ;
     RECT  11.7 28.715 12.618 28.787 ;
     RECT  0.144 28.891 0.162 28.957 ;
     RECT  0.144 28.957 0.558 29.021 ;
     RECT  0.54 29.021 0.558 29.117 ;
     RECT  2.304 28.715 10.797 29.461 ;
     RECT  2.304 29.461 11.07 29.605 ;
     RECT  11.808 28.787 12.618 29.605 ;
     RECT  14.184 28.751 14.238 29.707 ;
     RECT  13.644 29.707 14.238 29.899 ;
     RECT  13.536 29.899 14.238 30.101 ;
     RECT  2.304 29.605 12.618 30.145 ;
     RECT  13.644 30.101 14.238 30.181 ;
     RECT  2.304 30.145 12.654 30.299 ;
     RECT  0.144 30.619 0.162 30.749 ;
     RECT  13.644 30.181 14.31 30.989 ;
     RECT  2.304 30.299 12.582 31.181 ;
     RECT  4.824 31.181 12.582 31.261 ;
     RECT  13.644 30.989 14.238 31.649 ;
     RECT  13.644 31.649 13.77 31.771 ;
     RECT  13.608 31.771 13.77 31.829 ;
     RECT  13.644 31.829 13.77 31.997 ;
     RECT  2.304 31.181 3.978 31.999 ;
     RECT  4.824 31.261 12.618 31.999 ;
     RECT  2.304 31.999 12.618 32.188 ;
     RECT  13.644 31.997 13.662 32.779 ;
     RECT  14.94 31.891 14.958 32.779 ;
     RECT  2.304 32.188 12.654 33.269 ;
     RECT  0.54 33.583 0.558 33.677 ;
     RECT  13.644 32.779 14.958 33.677 ;
     RECT  10.515 33.269 12.618 33.881 ;
     RECT  10.515 33.881 11.25 33.917 ;
     RECT  12.024 33.881 12.618 34.051 ;
     RECT  2.304 33.269 9.774 34.079 ;
     RECT  10.515 33.917 11.178 34.079 ;
     RECT  10.515 34.079 10.89 34.123 ;
     RECT  13.644 33.677 13.662 34.501 ;
     RECT  14.868 33.677 14.958 34.501 ;
     RECT  10.368 34.123 10.89 34.933 ;
     RECT  10.044 34.933 10.89 35.005 ;
     RECT  10.044 35.005 11.286 35.041 ;
     RECT  12.024 34.051 12.654 35.041 ;
     RECT  13.644 34.501 14.958 35.429 ;
     RECT  10.044 35.041 12.654 35.659 ;
     RECT  13.644 35.429 14.274 35.659 ;
     RECT  2.304 34.079 9.198 35.851 ;
     RECT  10.044 35.659 14.274 35.851 ;
     RECT  2.304 35.851 14.274 35.879 ;
     RECT  2.304 35.879 12.618 35.969 ;
     RECT  0.144 35.899 0.162 36.029 ;
     RECT  2.304 35.969 9.306 36.383 ;
     RECT  7.02 36.383 9.306 36.509 ;
     RECT  13.644 35.879 14.274 36.715 ;
     RECT  7.815 36.509 9.306 36.779 ;
     RECT  10.476 35.969 12.618 36.931 ;
     RECT  10.332 36.931 12.618 37.049 ;
     RECT  13.608 36.715 14.274 37.049 ;
     RECT  2.304 36.383 6.03 37.129 ;
     RECT  2.304 37.129 6.282 37.201 ;
     RECT  7.02 36.509 7.038 37.201 ;
     RECT  2.304 37.201 7.038 37.435 ;
     RECT  7.815 36.779 9.198 37.435 ;
     RECT  10.476 37.049 12.618 37.597 ;
     RECT  13.644 37.049 14.274 37.597 ;
     RECT  10.476 37.597 12.69 37.625 ;
     RECT  10.515 37.625 12.69 38.101 ;
     RECT  13.644 37.597 14.31 38.201 ;
     RECT  2.304 37.435 9.198 38.479 ;
     RECT  10.515 38.101 12.762 38.479 ;
     RECT  14.148 38.201 14.31 38.641 ;
     RECT  2.304 38.479 12.762 38.669 ;
     RECT  9.972 38.669 12.762 38.741 ;
     RECT  9.972 38.741 12.654 38.939 ;
     RECT  14.148 38.641 14.958 39.005 ;
     RECT  10.332 38.939 12.654 39.209 ;
     RECT  14.22 39.005 14.958 39.437 ;
     RECT  10.515 39.209 12.654 39.757 ;
     RECT  10.515 39.757 12.762 39.784 ;
     RECT  10.515 39.784 13.086 39.821 ;
     RECT  14.22 39.437 14.238 39.865 ;
     RECT  10.515 39.821 12.762 39.893 ;
     RECT  10.515 39.893 12.654 40.261 ;
     RECT  10.476 40.261 12.654 40.289 ;
     RECT  10.476 40.289 12.618 40.361 ;
     RECT  14.184 39.865 14.238 40.603 ;
     RECT  0.144 41.035 0.162 41.165 ;
     RECT  10.515 40.361 12.618 41.251 ;
     RECT  13.644 40.603 14.238 41.251 ;
     RECT  10.26 41.251 12.618 41.279 ;
     RECT  13.644 41.251 14.958 41.441 ;
     RECT  2.304 38.669 9.198 41.521 ;
     RECT  10.26 41.279 12.582 41.521 ;
     RECT  2.304 41.521 12.582 41.639 ;
     RECT  10.044 41.639 12.582 41.981 ;
     RECT  10.26 41.981 12.582 42.179 ;
     RECT  10.332 42.179 12.582 42.449 ;
     RECT  14.22 41.441 14.958 42.449 ;
     RECT  10.515 42.449 12.582 42.565 ;
     RECT  2.304 41.639 9.198 42.601 ;
     RECT  2.304 42.601 9.306 42.719 ;
     RECT  10.515 42.565 12.654 42.907 ;
     RECT  13.644 42.475 13.662 42.907 ;
     RECT  10.515 42.907 13.662 43.061 ;
     RECT  2.304 42.719 9.198 43.565 ;
     RECT  10.515 43.061 12.798 43.681 ;
     RECT  13.608 43.061 13.662 44.141 ;
     RECT  10.332 43.681 12.798 44.189 ;
     RECT  10.332 44.189 12.762 44.411 ;
     RECT  10.332 44.411 12.69 44.419 ;
     RECT  2.304 43.565 3.222 44.491 ;
     RECT  3.96 43.565 9.198 44.491 ;
     RECT  14.94 42.449 14.958 44.573 ;
     RECT  10.116 44.419 12.69 44.609 ;
     RECT  0.144 44.539 0.162 44.669 ;
     RECT  13.644 44.141 13.662 44.725 ;
     RECT  13.644 44.725 14.238 44.971 ;
     RECT  13.536 44.971 14.238 45.163 ;
     RECT  13.5 45.163 14.238 45.221 ;
     RECT  13.536 45.221 14.238 45.257 ;
     RECT  2.304 44.491 9.198 45.571 ;
     RECT  10.404 44.609 12.69 45.571 ;
     RECT  14.22 45.257 14.238 45.959 ;
     RECT  2.304 45.571 12.69 46.139 ;
     RECT  13.644 45.979 13.698 46.171 ;
     RECT  2.304 46.139 9.126 46.229 ;
     RECT  9.864 46.139 12.69 46.381 ;
     RECT  13.608 46.171 13.698 46.499 ;
     RECT  13.644 46.499 13.698 46.741 ;
     RECT  9.864 46.381 12.762 46.769 ;
     RECT  9.972 46.769 12.762 47.309 ;
     RECT  10.188 47.309 12.762 47.381 ;
     RECT  11.52 47.381 12.762 47.453 ;
     RECT  11.52 47.453 12.618 47.579 ;
     RECT  13.644 46.741 14.238 47.695 ;
     RECT  13.608 47.695 14.238 47.885 ;
     RECT  0.144 48.043 0.162 48.173 ;
     RECT  2.304 46.229 8.874 48.235 ;
     RECT  2.304 48.235 8.946 48.271 ;
     RECT  10.188 47.381 10.797 48.271 ;
     RECT  13.644 47.885 14.238 48.299 ;
     RECT  2.304 48.271 10.854 48.389 ;
     RECT  2.304 48.389 9.306 48.425 ;
     RECT  11.772 47.579 12.618 48.433 ;
     RECT  10.515 48.389 10.854 48.505 ;
     RECT  11.772 48.433 12.654 48.505 ;
     RECT  14.94 48.433 14.958 48.509 ;
     RECT  2.304 48.425 9.162 48.659 ;
     RECT  10.515 48.505 12.654 48.659 ;
     RECT  13.644 48.299 13.662 49.099 ;
     RECT  10.515 48.659 10.797 49.441 ;
     RECT  11.556 48.659 12.618 49.441 ;
     RECT  2.304 48.659 8.91 49.855 ;
     RECT  10.515 49.441 12.618 49.915 ;
     RECT  13.644 49.099 14.238 49.915 ;
     RECT  10.515 49.915 14.238 50.117 ;
     RECT  10.515 50.117 12.654 50.323 ;
     RECT  10.224 50.323 12.654 50.431 ;
     RECT  9.972 50.431 12.654 50.621 ;
     RECT  2.304 49.855 8.946 50.701 ;
     RECT  10.44 50.621 12.654 50.819 ;
     RECT  2.304 50.701 9.594 50.855 ;
     RECT  13.536 50.117 14.238 50.999 ;
     RECT  13.644 50.999 14.238 51.115 ;
     RECT  10.44 50.819 12.618 51.125 ;
     RECT  13.644 51.115 14.274 51.197 ;
     RECT  13.644 51.197 14.238 51.269 ;
     RECT  10.44 51.125 12.51 51.511 ;
     RECT  2.304 50.855 8.946 51.629 ;
     RECT  9.756 51.511 12.51 51.629 ;
     RECT  9.756 51.629 12.438 51.701 ;
     RECT  13.68 51.269 14.238 52.051 ;
     RECT  9.864 51.701 12.438 52.411 ;
     RECT  9.864 52.411 12.582 52.439 ;
     RECT  10.515 52.439 12.582 52.583 ;
     RECT  2.304 51.629 8.838 52.861 ;
     RECT  2.304 52.861 9.594 52.979 ;
     RECT  2.304 52.979 8.874 53.249 ;
     RECT  13.644 52.051 14.238 53.329 ;
     RECT  10.515 52.583 12.294 53.401 ;
     RECT  10.515 53.401 12.762 53.519 ;
     RECT  10.515 53.519 12.618 53.671 ;
     RECT  13.644 53.329 14.274 53.671 ;
     RECT  10.404 53.671 12.618 53.941 ;
     RECT  13.644 53.671 14.31 54.131 ;
     RECT  14.22 54.131 14.31 54.235 ;
     RECT  10.332 53.941 12.618 54.481 ;
     RECT  10.296 54.481 12.654 54.599 ;
     RECT  10.296 54.599 10.926 54.671 ;
     RECT  10.296 54.671 10.89 54.679 ;
     RECT  2.304 53.249 8.838 54.715 ;
     RECT  2.304 54.715 8.874 54.751 ;
     RECT  9.792 54.679 10.89 54.751 ;
     RECT  2.304 54.751 10.89 54.905 ;
     RECT  11.808 54.599 12.654 55.049 ;
     RECT  0.144 55.051 0.162 55.181 ;
     RECT  14.22 54.235 14.958 55.243 ;
     RECT  13.644 55.243 14.958 55.319 ;
     RECT  10.224 54.905 10.89 55.453 ;
     RECT  12.276 55.049 12.654 55.517 ;
     RECT  12.276 55.517 12.582 55.589 ;
     RECT  2.34 54.905 8.838 55.675 ;
     RECT  13.644 55.319 14.238 55.675 ;
     RECT  10.224 55.453 11.538 55.795 ;
     RECT  12.276 55.589 12.546 55.795 ;
     RECT  10.224 55.795 12.546 55.831 ;
     RECT  9.684 55.831 12.546 55.949 ;
     RECT  9.9 55.949 12.546 56.021 ;
     RECT  13.608 55.675 14.238 56.129 ;
     RECT  9.9 56.021 10.818 56.219 ;
     RECT  11.772 56.021 12.546 56.219 ;
     RECT  0.216 56.107 0.234 56.285 ;
     RECT  13.644 56.129 14.238 56.333 ;
     RECT  11.88 56.219 12.546 56.335 ;
     RECT  2.304 55.675 8.838 57.073 ;
     RECT  11.88 56.335 12.618 57.073 ;
     RECT  10.404 56.219 10.818 57.145 ;
     RECT  10.404 57.145 10.854 57.271 ;
     RECT  11.7 57.073 12.618 57.271 ;
     RECT  14.22 56.333 14.238 57.307 ;
     RECT  2.304 57.073 8.874 57.407 ;
     RECT  4.824 57.407 8.874 57.415 ;
     RECT  4.824 57.415 8.946 57.451 ;
     RECT  10.404 57.271 12.618 57.451 ;
     RECT  13.536 57.307 14.238 57.479 ;
     RECT  4.824 57.451 9.306 57.569 ;
     RECT  10.332 57.451 12.618 57.569 ;
     RECT  13.644 57.479 14.238 58.117 ;
     RECT  13.644 58.117 14.958 58.157 ;
     RECT  2.304 57.407 4.086 58.261 ;
     RECT  4.824 57.569 8.91 58.261 ;
     RECT  2.304 58.261 8.91 58.415 ;
     RECT  13.644 58.157 14.238 58.451 ;
     RECT  0.144 58.363 0.162 58.493 ;
     RECT  10.515 57.569 12.618 58.495 ;
     RECT  14.184 58.451 14.238 58.987 ;
     RECT  2.304 58.415 8.874 59.189 ;
     RECT  14.184 58.987 14.958 59.189 ;
     RECT  2.304 59.189 8.802 59.261 ;
     RECT  10.515 58.495 12.654 59.305 ;
     RECT  2.304 59.261 8.097 59.495 ;
     RECT  4.752 59.495 8.097 59.567 ;
     RECT  4.752 59.567 6.57 59.603 ;
     RECT  6.228 59.603 6.57 59.729 ;
     RECT  7.308 59.567 8.097 59.729 ;
     RECT  10.515 59.305 12.69 59.729 ;
     RECT  2.304 59.495 3.906 59.765 ;
     RECT  6.228 59.729 6.246 60.269 ;
     RECT  14.22 59.189 14.958 60.269 ;
     RECT  2.304 59.765 3.582 60.305 ;
     RECT  2.415 60.305 3.582 60.539 ;
     RECT  10.515 59.729 12.474 60.539 ;
     RECT  14.904 60.269 14.958 60.539 ;
     RECT  11.52 60.539 12.474 60.655 ;
     RECT  14.904 60.539 14.922 60.809 ;
     RECT  11.52 60.655 12.618 60.845 ;
     RECT  4.752 59.603 5.397 61.079 ;
     RECT  11.52 60.845 11.754 61.079 ;
     RECT  11.736 61.079 11.754 61.349 ;
     RECT  12.6 60.845 12.618 61.349 ;
     RECT  2.415 60.539 2.697 62.387 ;
     RECT  5.115 61.079 5.397 62.387 ;
     RECT  7.815 59.729 8.097 62.387 ;
     RECT  10.515 60.539 10.797 62.387 ;
     RECT  2.415 62.387 2.505 62.657 ;
     RECT  5.115 62.387 5.205 62.657 ;
     RECT  7.815 62.387 7.905 62.657 ;
     RECT  10.515 62.387 10.605 62.657 ;
    LAYER M4 ;
     RECT  0.085 1.392 0.108 1.416 ;
     RECT  0.085 32.496 0.108 32.52 ;
     RECT  0.108 5.424 0.173 59.4 ;
     RECT  0.173 5.616 2.408 59.4 ;
     RECT  2.408 2.148 2.512 62.652 ;
     RECT  2.512 2.418 2.704 62.382 ;
     RECT  2.704 13.584 2.765 13.848 ;
     RECT  2.704 31.92 2.765 37.032 ;
     RECT  2.704 38.256 2.765 41.256 ;
     RECT  2.704 49.488 2.765 53.64 ;
     RECT  2.704 58.128 2.765 59.208 ;
     RECT  2.765 31.92 2.801 36.024 ;
     RECT  2.765 38.256 2.801 38.808 ;
     RECT  2.704 42.72 2.801 45.192 ;
     RECT  2.704 46.752 2.801 48.168 ;
     RECT  2.704 18.48 2.837 19.992 ;
     RECT  2.704 24.96 2.837 25.512 ;
     RECT  2.704 26.64 2.837 29.016 ;
     RECT  2.801 31.92 2.837 34.392 ;
     RECT  2.801 42.72 2.837 44.664 ;
     RECT  2.765 49.488 2.837 53.016 ;
     RECT  2.704 55.152 2.837 57.144 ;
     RECT  2.704 11.664 2.873 11.784 ;
     RECT  2.765 58.464 2.909 59.208 ;
     RECT  2.837 28.992 3.017 29.016 ;
     RECT  2.704 30.24 3.017 30.648 ;
     RECT  2.765 40.416 3.017 41.16 ;
     RECT  2.837 26.64 3.053 27.336 ;
     RECT  2.704 15.984 3.089 17.16 ;
     RECT  2.801 38.256 3.197 38.28 ;
     RECT  2.837 49.488 3.197 52.488 ;
     RECT  2.704 7.824 3.299 8.76 ;
     RECT  2.837 25.488 3.305 25.512 ;
     RECT  2.704 6 3.413 6.84 ;
     RECT  2.704 9.792 3.449 10.68 ;
     RECT  2.765 13.584 3.449 13.608 ;
     RECT  2.837 44.64 3.449 44.664 ;
     RECT  2.837 55.152 3.449 56.28 ;
     RECT  2.801 48.144 3.521 48.168 ;
     RECT  2.873 11.76 3.557 11.784 ;
     RECT  2.837 18.48 3.557 18.504 ;
     RECT  2.704 21.408 3.557 22.008 ;
     RECT  3.089 17.136 3.629 17.16 ;
     RECT  2.704 23.376 3.629 23.88 ;
     RECT  3.449 9.792 3.665 9.816 ;
     RECT  3.557 21.408 3.665 21.432 ;
     RECT  3.017 40.848 3.665 41.16 ;
     RECT  2.837 42.72 3.665 43.56 ;
     RECT  3.053 27.312 3.701 27.336 ;
     RECT  3.089 15.984 3.877 16.008 ;
     RECT  2.837 31.92 3.932 33.144 ;
     RECT  2.837 34.368 3.932 34.392 ;
     RECT  2.801 36 3.949 36.024 ;
     RECT  3.913 54.624 3.949 54.744 ;
     RECT  3.932 31.92 3.973 34.392 ;
     RECT  3.973 31.92 4.019 34.68 ;
     RECT  3.665 42.72 4.061 42.744 ;
     RECT  4.019 31.92 4.097 33.048 ;
     RECT  3.197 50.16 4.124 52.488 ;
     RECT  3.949 54.096 4.124 54.744 ;
     RECT  4.019 34.368 4.127 34.68 ;
     RECT  3.949 35.76 4.127 36.024 ;
     RECT  3.449 55.776 4.165 56.28 ;
     RECT  3.913 45.168 4.417 45.192 ;
     RECT  4.273 13.632 4.489 13.656 ;
     RECT  4.489 13.632 4.501 13.704 ;
     RECT  4.501 13.056 4.525 13.704 ;
     RECT  4.124 50.16 4.789 54.744 ;
     RECT  4.165 55.776 4.789 56.52 ;
     RECT  4.309 29.232 4.813 29.256 ;
     RECT  3.413 6.288 5.108 6.312 ;
     RECT  4.849 7.344 5.108 7.368 ;
     RECT  4.525 13.056 5.108 13.848 ;
     RECT  3.877 15.456 5.108 16.008 ;
     RECT  2.837 19.632 5.108 19.992 ;
     RECT  3.733 21.12 5.108 21.144 ;
     RECT  3.629 23.376 5.108 23.4 ;
     RECT  4.489 26.64 5.108 26.664 ;
     RECT  4.813 28.416 5.108 29.256 ;
     RECT  3.017 30.24 5.108 30.264 ;
     RECT  4.097 31.92 5.108 32.52 ;
     RECT  4.127 34.368 5.108 36.024 ;
     RECT  2.765 37.008 5.108 37.032 ;
     RECT  4.129 39.312 5.108 39.336 ;
     RECT  3.665 40.848 5.108 40.872 ;
     RECT  4.309 42.192 5.108 42.216 ;
     RECT  4.417 44.352 5.108 45.192 ;
     RECT  2.801 46.752 5.108 46.776 ;
     RECT  4.813 48.72 5.108 48.744 ;
     RECT  4.789 50.16 5.108 56.52 ;
     RECT  2.909 59.184 5.108 59.208 ;
     RECT  5.108 2.148 5.212 62.652 ;
     RECT  5.212 2.418 5.404 62.382 ;
     RECT  5.404 22.224 5.537 23.64 ;
     RECT  5.404 13.008 5.651 13.848 ;
     RECT  5.404 50.544 5.717 52.488 ;
     RECT  5.404 26.64 5.789 26.664 ;
     RECT  5.404 15.168 5.795 16.536 ;
     RECT  5.651 13.056 5.833 13.848 ;
     RECT  5.404 47.28 5.969 47.304 ;
     RECT  5.404 39.312 6.035 39.336 ;
     RECT  5.795 15.168 6.041 15.48 ;
     RECT  5.404 40.848 6.077 42.408 ;
     RECT  5.404 44.352 6.113 45.192 ;
     RECT  5.404 54.048 6.149 54.744 ;
     RECT  5.404 29.04 6.257 29.256 ;
     RECT  6.077 42.192 6.257 42.408 ;
     RECT  5.795 16.512 6.275 16.536 ;
     RECT  6.257 29.04 6.275 29.208 ;
     RECT  6.257 42.384 6.275 42.408 ;
     RECT  5.404 48.624 6.275 49.512 ;
     RECT  5.537 23.52 6.329 23.64 ;
     RECT  6.113 44.352 6.329 44.904 ;
     RECT  5.833 13.536 6.365 13.848 ;
     RECT  5.404 19.008 6.38 21.144 ;
     RECT  6.38 18.192 6.397 21.144 ;
     RECT  5.537 22.224 6.397 22.248 ;
     RECT  5.404 7.344 6.437 7.368 ;
     RECT  6.397 18.192 6.437 22.248 ;
     RECT  6.275 29.04 6.437 29.064 ;
     RECT  5.404 36 6.437 36.024 ;
     RECT  6.275 48.72 6.437 49.512 ;
     RECT  5.717 50.544 6.437 52.44 ;
     RECT  6.437 18.192 6.467 21.816 ;
     RECT  6.467 18.816 6.481 21.816 ;
     RECT  5.404 34.368 6.541 34.392 ;
     RECT  6.481 19.008 6.581 21.816 ;
     RECT  6.541 34.08 6.649 34.392 ;
     RECT  6.149 54.048 7.693 54.696 ;
     RECT  6.365 13.536 7.808 13.656 ;
     RECT  6.041 15.168 7.808 15.192 ;
     RECT  6.581 19.008 7.808 19.032 ;
     RECT  6.581 20.832 7.808 21.816 ;
     RECT  6.397 24.144 7.808 24.168 ;
     RECT  5.404 31.776 7.808 33.048 ;
     RECT  6.649 34.08 7.808 35.352 ;
     RECT  6.077 40.848 7.808 40.872 ;
     RECT  6.329 44.88 7.808 44.904 ;
     RECT  7.081 46.464 7.808 46.488 ;
     RECT  6.437 49.488 7.808 49.512 ;
     RECT  6.437 50.544 7.808 50.568 ;
     RECT  6.437 51.648 7.808 52.44 ;
     RECT  7.693 53.904 7.808 54.696 ;
     RECT  5.404 59.184 7.808 59.208 ;
     RECT  7.808 2.148 7.912 62.652 ;
     RECT  7.912 2.418 8.104 62.382 ;
     RECT  8.104 34.08 8.129 34.92 ;
     RECT  8.104 15.984 8.165 16.008 ;
     RECT  8.104 20.88 8.165 22.488 ;
     RECT  8.104 24.144 8.165 25.032 ;
     RECT  8.104 38.16 8.165 39.768 ;
     RECT  8.104 50.544 8.165 54.696 ;
     RECT  8.104 58.128 8.165 58.152 ;
     RECT  8.129 34.08 8.201 34.104 ;
     RECT  8.104 40.848 8.201 40.872 ;
     RECT  8.165 50.688 8.201 54.696 ;
     RECT  8.104 59.184 8.201 59.208 ;
     RECT  8.165 20.928 8.237 20.952 ;
     RECT  8.104 12.24 8.243 13.704 ;
     RECT  8.165 25.008 8.243 25.032 ;
     RECT  8.104 26.064 8.243 26.808 ;
     RECT  8.104 28.464 8.243 29.064 ;
     RECT  8.165 38.16 8.243 38.808 ;
     RECT  8.104 42.48 8.243 47.352 ;
     RECT  8.201 50.688 8.243 53.832 ;
     RECT  8.243 50.688 8.245 50.712 ;
     RECT  8.243 12.24 8.291 12.264 ;
     RECT  8.243 13.632 8.291 13.704 ;
     RECT  8.104 30.816 8.669 32.52 ;
     RECT  8.669 31.488 9.461 32.52 ;
     RECT  9.461 31.488 9.709 31.944 ;
     RECT  9.685 6.864 10.508 6.888 ;
     RECT  8.291 13.632 10.508 13.656 ;
     RECT  8.243 29.04 10.508 29.064 ;
     RECT  9.709 30.768 10.508 31.944 ;
     RECT  10.508 2.148 10.612 62.652 ;
     RECT  10.612 2.418 10.804 62.382 ;
     RECT  10.804 52.272 11.837 52.296 ;
     RECT  12.625 35.088 13.057 35.112 ;
     RECT  12.517 42.672 13.057 42.696 ;
     RECT  12.805 6.432 13.093 6.456 ;
     RECT  12.661 45.792 13.489 45.816 ;
     RECT  13.057 9.504 13.525 9.528 ;
     RECT  12.589 14.064 13.525 14.088 ;
     RECT  12.769 44.16 13.525 44.184 ;
     RECT  13.489 45.168 13.525 45.816 ;
     RECT  13.057 49.92 13.525 49.944 ;
     RECT  13.057 19.008 13.597 19.032 ;
     RECT  13.525 20.448 13.597 20.472 ;
     RECT  12.625 32.4 13.597 32.424 ;
     RECT  13.057 42.672 13.597 42.936 ;
     RECT  13.525 44.16 13.597 45.816 ;
     RECT  12.733 47.424 13.597 47.448 ;
     RECT  13.525 9.312 13.633 9.528 ;
     RECT  13.597 10.56 13.633 10.584 ;
     RECT  13.525 14.064 13.633 14.28 ;
     RECT  13.057 15.696 13.633 15.72 ;
     RECT  12.589 17.328 13.633 17.352 ;
     RECT  13.597 19.008 13.633 20.472 ;
     RECT  13.057 24.768 13.633 24.792 ;
     RECT  13.057 27.456 13.633 28.296 ;
     RECT  13.525 29.904 13.633 29.928 ;
     RECT  13.597 31.776 13.633 32.424 ;
     RECT  13.057 35.088 13.633 35.688 ;
     RECT  13.597 36.72 13.633 36.744 ;
     RECT  13.057 39.792 13.633 39.816 ;
     RECT  13.597 42.672 13.633 46.2 ;
     RECT  13.597 47.424 13.633 47.88 ;
     RECT  13.525 49.92 13.633 50.76 ;
     RECT  13.597 55.68 13.633 55.704 ;
     RECT  13.525 57.312 13.633 57.336 ;
     RECT  13.633 9.12 13.669 9.528 ;
     RECT  13.633 10.56 13.669 10.776 ;
     RECT  13.633 11.76 13.669 12.024 ;
     RECT  13.633 13.008 13.669 13.032 ;
     RECT  13.633 23.136 13.669 23.352 ;
     RECT  13.633 26.016 13.669 26.04 ;
     RECT  13.633 27.456 13.669 28.68 ;
     RECT  13.633 52.176 13.669 53.832 ;
     RECT  13.633 31.584 14.137 38.184 ;
     RECT  13.633 39.792 14.137 41.256 ;
     RECT  13.093 6.192 14.173 6.456 ;
     RECT  13.525 7.872 14.173 7.896 ;
     RECT  13.669 9.12 14.173 10.776 ;
     RECT  13.669 11.76 14.173 13.032 ;
     RECT  13.633 14.064 14.173 15.72 ;
     RECT  13.633 16.944 14.173 21.912 ;
     RECT  13.669 22.896 14.173 23.352 ;
     RECT  13.633 24.336 14.173 24.984 ;
     RECT  13.669 26.016 14.173 28.68 ;
     RECT  13.633 29.712 14.173 30.552 ;
     RECT  14.137 31.584 14.173 41.256 ;
     RECT  13.633 57.312 14.173 57.96 ;
     RECT  14.173 6 14.209 10.776 ;
     RECT  14.173 11.76 14.209 41.256 ;
     RECT  13.633 42.48 14.209 50.76 ;
     RECT  13.669 51.984 14.209 53.832 ;
     RECT  13.633 55.248 14.209 56.328 ;
     RECT  14.173 57.312 14.209 58.776 ;
     RECT  14.209 5.808 14.893 59.208 ;
     RECT  14.893 5.616 14.929 59.4 ;
     RECT  14.929 5.424 15.036 59.4 ;
    LAYER M5 ;
     RECT  0.192 1.285 0.216 1.381 ;
     RECT  0.096 1.381 0.216 1.427 ;
     RECT  2.4 2.137 2.52 2.151 ;
     RECT  5.1 2.137 5.22 2.151 ;
     RECT  7.8 2.137 7.92 2.151 ;
     RECT  9.696 2.137 10.62 2.151 ;
     RECT  2.4 2.151 2.712 6.805 ;
     RECT  9.696 2.151 10.812 6.899 ;
     RECT  2.4 6.805 3.288 8.771 ;
     RECT  7.8 2.151 8.112 12.229 ;
     RECT  5.1 2.151 5.412 12.997 ;
     RECT  5.1 12.997 5.64 13.045 ;
     RECT  4.512 13.045 5.784 13.715 ;
     RECT  7.8 12.229 8.28 13.715 ;
     RECT  5.1 13.715 5.784 16.501 ;
     RECT  5.1 16.501 6.264 18.181 ;
     RECT  5.1 18.181 6.456 18.851 ;
     RECT  5.1 18.851 6.408 22.259 ;
     RECT  7.8 13.715 8.232 26.819 ;
     RECT  7.8 26.819 8.112 28.453 ;
     RECT  7.8 28.453 8.232 29.075 ;
     RECT  5.1 22.259 6.264 29.219 ;
     RECT  5.1 29.219 6.024 32.243 ;
     RECT  0.096 1.427 0.12 32.389 ;
     RECT  0.096 32.389 0.216 32.531 ;
     RECT  5.1 32.243 5.928 33.059 ;
     RECT  0.192 32.531 0.216 33.155 ;
     RECT  0.144 34.021 0.168 34.403 ;
     RECT  3.984 33.013 4.008 34.645 ;
     RECT  5.1 33.059 5.784 34.645 ;
     RECT  3.984 34.645 5.784 34.691 ;
     RECT  7.8 29.075 8.112 34.885 ;
     RECT  6.816 34.885 8.112 35.363 ;
     RECT  4.128 34.691 5.784 35.795 ;
     RECT  4.176 35.795 5.784 35.987 ;
     RECT  7.8 35.363 8.112 38.149 ;
     RECT  0.144 37.717 0.168 38.291 ;
     RECT  7.8 38.149 8.232 38.819 ;
     RECT  5.1 35.987 5.784 39.301 ;
     RECT  5.1 39.301 6.024 42.373 ;
     RECT  7.8 38.819 8.112 42.469 ;
     RECT  7.8 42.469 8.232 47.363 ;
     RECT  5.1 42.373 6.264 49.523 ;
     RECT  2.4 8.771 2.712 50.149 ;
     RECT  7.8 47.363 8.112 50.677 ;
     RECT  2.4 50.149 3.24 50.723 ;
     RECT  5.1 49.523 5.976 51.971 ;
     RECT  5.1 51.971 5.412 52.213 ;
     RECT  7.8 50.677 8.232 53.843 ;
     RECT  4.176 52.213 5.412 54.179 ;
     RECT  3.936 54.613 3.96 54.755 ;
     RECT  5.1 54.179 5.412 55.237 ;
     RECT  4.8 55.237 5.412 55.765 ;
     RECT  4.176 55.765 5.412 56.531 ;
     RECT  2.4 50.723 2.712 62.649 ;
     RECT  5.1 56.531 5.412 62.649 ;
     RECT  7.8 53.843 8.112 62.649 ;
     RECT  10.5 6.899 10.812 62.649 ;
     RECT  2.4 62.649 2.52 62.663 ;
     RECT  5.1 62.649 5.22 62.663 ;
     RECT  7.8 62.649 7.92 62.663 ;
     RECT  10.5 62.649 10.62 62.663 ;
     RECT  6.456 18.181 7.8 18.851 ;
     RECT  6.408 18.851 7.8 22.259 ;
     RECT  0.144 32.531 0.192 32.544 ;
     RECT  0.186 32.544 0.192 32.664 ;
     RECT  0.144 32.664 0.192 32.736 ;
     RECT  0.186 32.736 0.192 32.856 ;
     RECT  0.144 32.856 0.192 32.976 ;
     RECT  0.186 32.976 0.192 33.096 ;
     RECT  2.712 33.013 3.984 34.691 ;
     RECT  4.008 33.013 5.1 34.645 ;
     RECT  0.144 33.096 0.192 33.155 ;
     RECT  0.144 33.155 0.168 33.168 ;
     RECT  0.144 33.288 0.168 33.36 ;
     RECT  0.144 33.48 0.168 33.6 ;
     RECT  0.144 33.72 0.168 33.792 ;
     RECT  0.144 33.912 0.168 33.984 ;
     RECT  2.712 34.691 4.128 35.795 ;
     RECT  5.784 34.885 6.816 35.363 ;
     RECT  2.712 35.795 4.176 35.987 ;
     RECT  2.712 50.723 3.24 52.213 ;
     RECT  2.712 52.213 4.176 54.179 ;
     RECT  2.712 54.179 5.1 54.613 ;
     RECT  2.712 54.613 3.936 54.755 ;
     RECT  3.96 54.613 5.1 54.755 ;
     RECT  2.712 54.755 5.1 55.237 ;
     RECT  2.712 55.237 4.8 55.765 ;
     RECT  2.712 55.765 4.176 56.531 ;
  END
END qkh_packet_v263
END LIBRARY
